VERSION 5.8 ;
BUSBITCHARS "[]" ;
DIVIDERCHAR "/" ;
UNITS
    DATABASE MICRONS 1000 ;
END UNITS

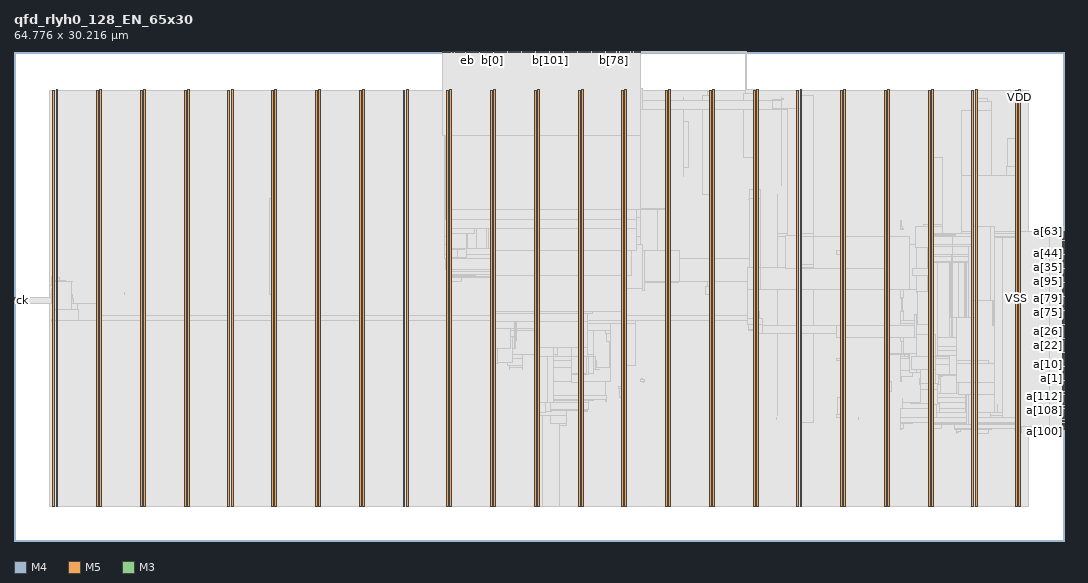
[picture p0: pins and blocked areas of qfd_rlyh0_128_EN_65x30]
MACRO qfd_rlyh0_128_EN_65x30
  FOREIGN qfd_rlyh0_128_EN_65x30 0 0 ;
  CLASS BLOCK ;
  SIZE 64.776 BY 30.216 ;
  PIN a[0]
    DIRECTION INPUT ;
    USE SIGNAL ;
    PORT
      LAYER M4 ;
        RECT  64.692 9.936 64.776 9.96 ;
    END
  END a[0]
  PIN a[100]
    DIRECTION INPUT ;
    USE SIGNAL ;
    PORT
      LAYER M4 ;
        RECT  64.692 7.248 64.776 7.272 ;
    END
  END a[100]
  PIN a[101]
    DIRECTION INPUT ;
    USE SIGNAL ;
    PORT
      LAYER M4 ;
        RECT  64.692 7.344 64.776 7.368 ;
    END
  END a[101]
  PIN a[102]
    DIRECTION INPUT ;
    USE SIGNAL ;
    PORT
      LAYER M4 ;
        RECT  64.692 7.44 64.776 7.464 ;
    END
  END a[102]
  PIN a[103]
    DIRECTION INPUT ;
    USE SIGNAL ;
    PORT
      LAYER M4 ;
        RECT  64.692 7.536 64.776 7.56 ;
    END
  END a[103]
  PIN a[104]
    DIRECTION INPUT ;
    USE SIGNAL ;
    PORT
      LAYER M4 ;
        RECT  64.692 7.632 64.776 7.656 ;
    END
  END a[104]
  PIN a[105]
    DIRECTION INPUT ;
    USE SIGNAL ;
    PORT
      LAYER M4 ;
        RECT  64.692 7.728 64.776 7.752 ;
    END
  END a[105]
  PIN a[106]
    DIRECTION INPUT ;
    USE SIGNAL ;
    PORT
      LAYER M4 ;
        RECT  64.692 7.824 64.776 7.848 ;
    END
  END a[106]
  PIN a[107]
    DIRECTION INPUT ;
    USE SIGNAL ;
    PORT
      LAYER M4 ;
        RECT  64.692 7.92 64.776 7.944 ;
    END
  END a[107]
  PIN a[108]
    DIRECTION INPUT ;
    USE SIGNAL ;
    PORT
      LAYER M4 ;
        RECT  64.692 8.016 64.776 8.04 ;
    END
  END a[108]
  PIN a[109]
    DIRECTION INPUT ;
    USE SIGNAL ;
    PORT
      LAYER M4 ;
        RECT  64.692 8.112 64.776 8.136 ;
    END
  END a[109]
  PIN a[10]
    DIRECTION INPUT ;
    USE SIGNAL ;
    PORT
      LAYER M4 ;
        RECT  64.692 10.896 64.776 10.92 ;
    END
  END a[10]
  PIN a[110]
    DIRECTION INPUT ;
    USE SIGNAL ;
    PORT
      LAYER M4 ;
        RECT  64.692 8.208 64.776 8.232 ;
    END
  END a[110]
  PIN a[111]
    DIRECTION INPUT ;
    USE SIGNAL ;
    PORT
      LAYER M4 ;
        RECT  64.692 8.304 64.776 8.328 ;
    END
  END a[111]
  PIN a[112]
    DIRECTION INPUT ;
    USE SIGNAL ;
    PORT
      LAYER M4 ;
        RECT  64.692 8.4 64.776 8.424 ;
    END
  END a[112]
  PIN a[113]
    DIRECTION INPUT ;
    USE SIGNAL ;
    PORT
      LAYER M4 ;
        RECT  64.692 8.496 64.776 8.52 ;
    END
  END a[113]
  PIN a[114]
    DIRECTION INPUT ;
    USE SIGNAL ;
    PORT
      LAYER M4 ;
        RECT  64.692 8.592 64.776 8.616 ;
    END
  END a[114]
  PIN a[115]
    DIRECTION INPUT ;
    USE SIGNAL ;
    PORT
      LAYER M4 ;
        RECT  64.692 8.688 64.776 8.712 ;
    END
  END a[115]
  PIN a[116]
    DIRECTION INPUT ;
    USE SIGNAL ;
    PORT
      LAYER M4 ;
        RECT  64.692 8.784 64.776 8.808 ;
    END
  END a[116]
  PIN a[117]
    DIRECTION INPUT ;
    USE SIGNAL ;
    PORT
      LAYER M4 ;
        RECT  64.692 8.88 64.776 8.904 ;
    END
  END a[117]
  PIN a[118]
    DIRECTION INPUT ;
    USE SIGNAL ;
    PORT
      LAYER M4 ;
        RECT  64.692 8.976 64.776 9 ;
    END
  END a[118]
  PIN a[119]
    DIRECTION INPUT ;
    USE SIGNAL ;
    PORT
      LAYER M4 ;
        RECT  64.692 9.072 64.776 9.096 ;
    END
  END a[119]
  PIN a[11]
    DIRECTION INPUT ;
    USE SIGNAL ;
    PORT
      LAYER M4 ;
        RECT  64.692 10.992 64.776 11.016 ;
    END
  END a[11]
  PIN a[120]
    DIRECTION INPUT ;
    USE SIGNAL ;
    PORT
      LAYER M4 ;
        RECT  64.692 9.168 64.776 9.192 ;
    END
  END a[120]
  PIN a[121]
    DIRECTION INPUT ;
    USE SIGNAL ;
    PORT
      LAYER M4 ;
        RECT  64.692 9.264 64.776 9.288 ;
    END
  END a[121]
  PIN a[122]
    DIRECTION INPUT ;
    USE SIGNAL ;
    PORT
      LAYER M4 ;
        RECT  64.692 9.36 64.776 9.384 ;
    END
  END a[122]
  PIN a[123]
    DIRECTION INPUT ;
    USE SIGNAL ;
    PORT
      LAYER M4 ;
        RECT  64.692 9.456 64.776 9.48 ;
    END
  END a[123]
  PIN a[124]
    DIRECTION INPUT ;
    USE SIGNAL ;
    PORT
      LAYER M4 ;
        RECT  64.692 9.552 64.776 9.576 ;
    END
  END a[124]
  PIN a[125]
    DIRECTION INPUT ;
    USE SIGNAL ;
    PORT
      LAYER M4 ;
        RECT  64.692 9.648 64.776 9.672 ;
    END
  END a[125]
  PIN a[126]
    DIRECTION INPUT ;
    USE SIGNAL ;
    PORT
      LAYER M4 ;
        RECT  64.692 9.744 64.776 9.768 ;
    END
  END a[126]
  PIN a[127]
    DIRECTION INPUT ;
    USE SIGNAL ;
    PORT
      LAYER M4 ;
        RECT  64.692 9.84 64.776 9.864 ;
    END
  END a[127]
  PIN a[12]
    DIRECTION INPUT ;
    USE SIGNAL ;
    PORT
      LAYER M4 ;
        RECT  64.692 11.088 64.776 11.112 ;
    END
  END a[12]
  PIN a[13]
    DIRECTION INPUT ;
    USE SIGNAL ;
    PORT
      LAYER M4 ;
        RECT  64.692 11.184 64.776 11.208 ;
    END
  END a[13]
  PIN a[14]
    DIRECTION INPUT ;
    USE SIGNAL ;
    PORT
      LAYER M4 ;
        RECT  64.692 11.28 64.776 11.304 ;
    END
  END a[14]
  PIN a[15]
    DIRECTION INPUT ;
    USE SIGNAL ;
    PORT
      LAYER M4 ;
        RECT  64.692 11.376 64.776 11.4 ;
    END
  END a[15]
  PIN a[16]
    DIRECTION INPUT ;
    USE SIGNAL ;
    PORT
      LAYER M4 ;
        RECT  64.692 11.472 64.776 11.496 ;
    END
  END a[16]
  PIN a[17]
    DIRECTION INPUT ;
    USE SIGNAL ;
    PORT
      LAYER M4 ;
        RECT  64.692 11.568 64.776 11.592 ;
    END
  END a[17]
  PIN a[18]
    DIRECTION INPUT ;
    USE SIGNAL ;
    PORT
      LAYER M4 ;
        RECT  64.692 11.664 64.776 11.688 ;
    END
  END a[18]
  PIN a[19]
    DIRECTION INPUT ;
    USE SIGNAL ;
    PORT
      LAYER M4 ;
        RECT  64.692 11.76 64.776 11.784 ;
    END
  END a[19]
  PIN a[1]
    DIRECTION INPUT ;
    USE SIGNAL ;
    PORT
      LAYER M4 ;
        RECT  64.692 10.032 64.776 10.056 ;
    END
  END a[1]
  PIN a[20]
    DIRECTION INPUT ;
    USE SIGNAL ;
    PORT
      LAYER M4 ;
        RECT  64.692 11.856 64.776 11.88 ;
    END
  END a[20]
  PIN a[21]
    DIRECTION INPUT ;
    USE SIGNAL ;
    PORT
      LAYER M4 ;
        RECT  64.692 11.952 64.776 11.976 ;
    END
  END a[21]
  PIN a[22]
    DIRECTION INPUT ;
    USE SIGNAL ;
    PORT
      LAYER M4 ;
        RECT  64.692 12.048 64.776 12.072 ;
    END
  END a[22]
  PIN a[23]
    DIRECTION INPUT ;
    USE SIGNAL ;
    PORT
      LAYER M4 ;
        RECT  64.692 12.144 64.776 12.168 ;
    END
  END a[23]
  PIN a[24]
    DIRECTION INPUT ;
    USE SIGNAL ;
    PORT
      LAYER M4 ;
        RECT  64.692 12.24 64.776 12.264 ;
    END
  END a[24]
  PIN a[25]
    DIRECTION INPUT ;
    USE SIGNAL ;
    PORT
      LAYER M4 ;
        RECT  64.692 12.336 64.776 12.36 ;
    END
  END a[25]
  PIN a[26]
    DIRECTION INPUT ;
    USE SIGNAL ;
    PORT
      LAYER M4 ;
        RECT  64.692 12.432 64.776 12.456 ;
    END
  END a[26]
  PIN a[27]
    DIRECTION INPUT ;
    USE SIGNAL ;
    PORT
      LAYER M4 ;
        RECT  64.692 12.528 64.776 12.552 ;
    END
  END a[27]
  PIN a[28]
    DIRECTION INPUT ;
    USE SIGNAL ;
    PORT
      LAYER M4 ;
        RECT  64.692 12.624 64.776 12.648 ;
    END
  END a[28]
  PIN a[29]
    DIRECTION INPUT ;
    USE SIGNAL ;
    PORT
      LAYER M4 ;
        RECT  64.692 12.72 64.776 12.744 ;
    END
  END a[29]
  PIN a[2]
    DIRECTION INPUT ;
    USE SIGNAL ;
    PORT
      LAYER M4 ;
        RECT  64.692 10.128 64.776 10.152 ;
    END
  END a[2]
  PIN a[30]
    DIRECTION INPUT ;
    USE SIGNAL ;
    PORT
      LAYER M4 ;
        RECT  64.692 12.816 64.776 12.84 ;
    END
  END a[30]
  PIN a[31]
    DIRECTION INPUT ;
    USE SIGNAL ;
    PORT
      LAYER M4 ;
        RECT  64.692 12.912 64.776 12.936 ;
    END
  END a[31]
  PIN a[32]
    DIRECTION INPUT ;
    USE SIGNAL ;
    PORT
      LAYER M4 ;
        RECT  64.692 16.08 64.776 16.104 ;
    END
  END a[32]
  PIN a[33]
    DIRECTION INPUT ;
    USE SIGNAL ;
    PORT
      LAYER M4 ;
        RECT  64.692 16.176 64.776 16.2 ;
    END
  END a[33]
  PIN a[34]
    DIRECTION INPUT ;
    USE SIGNAL ;
    PORT
      LAYER M4 ;
        RECT  64.692 16.272 64.776 16.296 ;
    END
  END a[34]
  PIN a[35]
    DIRECTION INPUT ;
    USE SIGNAL ;
    PORT
      LAYER M4 ;
        RECT  64.692 16.368 64.776 16.392 ;
    END
  END a[35]
  PIN a[36]
    DIRECTION INPUT ;
    USE SIGNAL ;
    PORT
      LAYER M4 ;
        RECT  64.692 16.464 64.776 16.488 ;
    END
  END a[36]
  PIN a[37]
    DIRECTION INPUT ;
    USE SIGNAL ;
    PORT
      LAYER M4 ;
        RECT  64.692 16.56 64.776 16.584 ;
    END
  END a[37]
  PIN a[38]
    DIRECTION INPUT ;
    USE SIGNAL ;
    PORT
      LAYER M4 ;
        RECT  64.692 16.656 64.776 16.68 ;
    END
  END a[38]
  PIN a[39]
    DIRECTION INPUT ;
    USE SIGNAL ;
    PORT
      LAYER M4 ;
        RECT  64.692 16.752 64.776 16.776 ;
    END
  END a[39]
  PIN a[3]
    DIRECTION INPUT ;
    USE SIGNAL ;
    PORT
      LAYER M4 ;
        RECT  64.692 10.224 64.776 10.248 ;
    END
  END a[3]
  PIN a[40]
    DIRECTION INPUT ;
    USE SIGNAL ;
    PORT
      LAYER M4 ;
        RECT  64.692 16.848 64.776 16.872 ;
    END
  END a[40]
  PIN a[41]
    DIRECTION INPUT ;
    USE SIGNAL ;
    PORT
      LAYER M4 ;
        RECT  64.692 16.944 64.776 16.968 ;
    END
  END a[41]
  PIN a[42]
    DIRECTION INPUT ;
    USE SIGNAL ;
    PORT
      LAYER M4 ;
        RECT  64.692 17.04 64.776 17.064 ;
    END
  END a[42]
  PIN a[43]
    DIRECTION INPUT ;
    USE SIGNAL ;
    PORT
      LAYER M4 ;
        RECT  64.692 17.136 64.776 17.16 ;
    END
  END a[43]
  PIN a[44]
    DIRECTION INPUT ;
    USE SIGNAL ;
    PORT
      LAYER M4 ;
        RECT  64.692 17.232 64.776 17.256 ;
    END
  END a[44]
  PIN a[45]
    DIRECTION INPUT ;
    USE SIGNAL ;
    PORT
      LAYER M4 ;
        RECT  64.692 17.328 64.776 17.352 ;
    END
  END a[45]
  PIN a[46]
    DIRECTION INPUT ;
    USE SIGNAL ;
    PORT
      LAYER M4 ;
        RECT  64.692 17.424 64.776 17.448 ;
    END
  END a[46]
  PIN a[47]
    DIRECTION INPUT ;
    USE SIGNAL ;
    PORT
      LAYER M4 ;
        RECT  64.692 17.52 64.776 17.544 ;
    END
  END a[47]
  PIN a[48]
    DIRECTION INPUT ;
    USE SIGNAL ;
    PORT
      LAYER M4 ;
        RECT  64.692 17.616 64.776 17.64 ;
    END
  END a[48]
  PIN a[49]
    DIRECTION INPUT ;
    USE SIGNAL ;
    PORT
      LAYER M4 ;
        RECT  64.692 17.712 64.776 17.736 ;
    END
  END a[49]
  PIN a[4]
    DIRECTION INPUT ;
    USE SIGNAL ;
    PORT
      LAYER M4 ;
        RECT  64.692 10.32 64.776 10.344 ;
    END
  END a[4]
  PIN a[50]
    DIRECTION INPUT ;
    USE SIGNAL ;
    PORT
      LAYER M4 ;
        RECT  64.692 17.808 64.776 17.832 ;
    END
  END a[50]
  PIN a[51]
    DIRECTION INPUT ;
    USE SIGNAL ;
    PORT
      LAYER M4 ;
        RECT  64.692 17.904 64.776 17.928 ;
    END
  END a[51]
  PIN a[52]
    DIRECTION INPUT ;
    USE SIGNAL ;
    PORT
      LAYER M4 ;
        RECT  64.692 18 64.776 18.024 ;
    END
  END a[52]
  PIN a[53]
    DIRECTION INPUT ;
    USE SIGNAL ;
    PORT
      LAYER M4 ;
        RECT  64.692 18.096 64.776 18.12 ;
    END
  END a[53]
  PIN a[54]
    DIRECTION INPUT ;
    USE SIGNAL ;
    PORT
      LAYER M4 ;
        RECT  64.692 18.192 64.776 18.216 ;
    END
  END a[54]
  PIN a[55]
    DIRECTION INPUT ;
    USE SIGNAL ;
    PORT
      LAYER M4 ;
        RECT  64.692 18.288 64.776 18.312 ;
    END
  END a[55]
  PIN a[56]
    DIRECTION INPUT ;
    USE SIGNAL ;
    PORT
      LAYER M4 ;
        RECT  64.692 18.384 64.776 18.408 ;
    END
  END a[56]
  PIN a[57]
    DIRECTION INPUT ;
    USE SIGNAL ;
    PORT
      LAYER M4 ;
        RECT  64.692 18.48 64.776 18.504 ;
    END
  END a[57]
  PIN a[58]
    DIRECTION INPUT ;
    USE SIGNAL ;
    PORT
      LAYER M4 ;
        RECT  64.692 18.576 64.776 18.6 ;
    END
  END a[58]
  PIN a[59]
    DIRECTION INPUT ;
    USE SIGNAL ;
    PORT
      LAYER M4 ;
        RECT  64.692 18.672 64.776 18.696 ;
    END
  END a[59]
  PIN a[5]
    DIRECTION INPUT ;
    USE SIGNAL ;
    PORT
      LAYER M4 ;
        RECT  64.692 10.416 64.776 10.44 ;
    END
  END a[5]
  PIN a[60]
    DIRECTION INPUT ;
    USE SIGNAL ;
    PORT
      LAYER M4 ;
        RECT  64.692 18.768 64.776 18.792 ;
    END
  END a[60]
  PIN a[61]
    DIRECTION INPUT ;
    USE SIGNAL ;
    PORT
      LAYER M4 ;
        RECT  64.692 18.864 64.776 18.888 ;
    END
  END a[61]
  PIN a[62]
    DIRECTION INPUT ;
    USE SIGNAL ;
    PORT
      LAYER M4 ;
        RECT  64.692 18.96 64.776 18.984 ;
    END
  END a[62]
  PIN a[63]
    DIRECTION INPUT ;
    USE SIGNAL ;
    PORT
      LAYER M4 ;
        RECT  64.692 19.056 64.776 19.08 ;
    END
  END a[63]
  PIN a[64]
    DIRECTION INPUT ;
    USE SIGNAL ;
    PORT
      LAYER M4 ;
        RECT  64.692 13.008 64.776 13.032 ;
    END
  END a[64]
  PIN a[65]
    DIRECTION INPUT ;
    USE SIGNAL ;
    PORT
      LAYER M4 ;
        RECT  64.692 13.104 64.776 13.128 ;
    END
  END a[65]
  PIN a[66]
    DIRECTION INPUT ;
    USE SIGNAL ;
    PORT
      LAYER M4 ;
        RECT  64.692 13.2 64.776 13.224 ;
    END
  END a[66]
  PIN a[67]
    DIRECTION INPUT ;
    USE SIGNAL ;
    PORT
      LAYER M4 ;
        RECT  64.692 13.296 64.776 13.32 ;
    END
  END a[67]
  PIN a[68]
    DIRECTION INPUT ;
    USE SIGNAL ;
    PORT
      LAYER M4 ;
        RECT  64.692 13.392 64.776 13.416 ;
    END
  END a[68]
  PIN a[69]
    DIRECTION INPUT ;
    USE SIGNAL ;
    PORT
      LAYER M4 ;
        RECT  64.692 13.488 64.776 13.512 ;
    END
  END a[69]
  PIN a[6]
    DIRECTION INPUT ;
    USE SIGNAL ;
    PORT
      LAYER M4 ;
        RECT  64.692 10.512 64.776 10.536 ;
    END
  END a[6]
  PIN a[70]
    DIRECTION INPUT ;
    USE SIGNAL ;
    PORT
      LAYER M4 ;
        RECT  64.692 13.584 64.776 13.608 ;
    END
  END a[70]
  PIN a[71]
    DIRECTION INPUT ;
    USE SIGNAL ;
    PORT
      LAYER M4 ;
        RECT  64.692 13.68 64.776 13.704 ;
    END
  END a[71]
  PIN a[72]
    DIRECTION INPUT ;
    USE SIGNAL ;
    PORT
      LAYER M4 ;
        RECT  64.692 13.776 64.776 13.8 ;
    END
  END a[72]
  PIN a[73]
    DIRECTION INPUT ;
    USE SIGNAL ;
    PORT
      LAYER M4 ;
        RECT  64.692 13.872 64.776 13.896 ;
    END
  END a[73]
  PIN a[74]
    DIRECTION INPUT ;
    USE SIGNAL ;
    PORT
      LAYER M4 ;
        RECT  64.692 13.968 64.776 13.992 ;
    END
  END a[74]
  PIN a[75]
    DIRECTION INPUT ;
    USE SIGNAL ;
    PORT
      LAYER M4 ;
        RECT  64.692 14.064 64.776 14.088 ;
    END
  END a[75]
  PIN a[76]
    DIRECTION INPUT ;
    USE SIGNAL ;
    PORT
      LAYER M4 ;
        RECT  64.692 14.16 64.776 14.184 ;
    END
  END a[76]
  PIN a[77]
    DIRECTION INPUT ;
    USE SIGNAL ;
    PORT
      LAYER M4 ;
        RECT  64.692 14.256 64.776 14.28 ;
    END
  END a[77]
  PIN a[78]
    DIRECTION INPUT ;
    USE SIGNAL ;
    PORT
      LAYER M4 ;
        RECT  64.692 14.352 64.776 14.376 ;
    END
  END a[78]
  PIN a[79]
    DIRECTION INPUT ;
    USE SIGNAL ;
    PORT
      LAYER M4 ;
        RECT  64.692 14.448 64.776 14.472 ;
    END
  END a[79]
  PIN a[7]
    DIRECTION INPUT ;
    USE SIGNAL ;
    PORT
      LAYER M4 ;
        RECT  64.692 10.608 64.776 10.632 ;
    END
  END a[7]
  PIN a[80]
    DIRECTION INPUT ;
    USE SIGNAL ;
    PORT
      LAYER M4 ;
        RECT  64.692 14.544 64.776 14.568 ;
    END
  END a[80]
  PIN a[81]
    DIRECTION INPUT ;
    USE SIGNAL ;
    PORT
      LAYER M4 ;
        RECT  64.692 14.64 64.776 14.664 ;
    END
  END a[81]
  PIN a[82]
    DIRECTION INPUT ;
    USE SIGNAL ;
    PORT
      LAYER M4 ;
        RECT  64.692 14.736 64.776 14.76 ;
    END
  END a[82]
  PIN a[83]
    DIRECTION INPUT ;
    USE SIGNAL ;
    PORT
      LAYER M4 ;
        RECT  64.692 14.832 64.776 14.856 ;
    END
  END a[83]
  PIN a[84]
    DIRECTION INPUT ;
    USE SIGNAL ;
    PORT
      LAYER M4 ;
        RECT  64.692 14.928 64.776 14.952 ;
    END
  END a[84]
  PIN a[85]
    DIRECTION INPUT ;
    USE SIGNAL ;
    PORT
      LAYER M4 ;
        RECT  64.692 15.024 64.776 15.048 ;
    END
  END a[85]
  PIN a[86]
    DIRECTION INPUT ;
    USE SIGNAL ;
    PORT
      LAYER M4 ;
        RECT  64.692 15.12 64.776 15.144 ;
    END
  END a[86]
  PIN a[87]
    DIRECTION INPUT ;
    USE SIGNAL ;
    PORT
      LAYER M4 ;
        RECT  64.692 15.216 64.776 15.24 ;
    END
  END a[87]
  PIN a[88]
    DIRECTION INPUT ;
    USE SIGNAL ;
    PORT
      LAYER M4 ;
        RECT  64.692 15.312 64.776 15.336 ;
    END
  END a[88]
  PIN a[89]
    DIRECTION INPUT ;
    USE SIGNAL ;
    PORT
      LAYER M4 ;
        RECT  64.692 15.408 64.776 15.432 ;
    END
  END a[89]
  PIN a[8]
    DIRECTION INPUT ;
    USE SIGNAL ;
    PORT
      LAYER M4 ;
        RECT  64.692 10.704 64.776 10.728 ;
    END
  END a[8]
  PIN a[90]
    DIRECTION INPUT ;
    USE SIGNAL ;
    PORT
      LAYER M4 ;
        RECT  64.692 15.504 64.776 15.528 ;
    END
  END a[90]
  PIN a[91]
    DIRECTION INPUT ;
    USE SIGNAL ;
    PORT
      LAYER M4 ;
        RECT  64.692 15.6 64.776 15.624 ;
    END
  END a[91]
  PIN a[92]
    DIRECTION INPUT ;
    USE SIGNAL ;
    PORT
      LAYER M4 ;
        RECT  64.692 15.696 64.776 15.72 ;
    END
  END a[92]
  PIN a[93]
    DIRECTION INPUT ;
    USE SIGNAL ;
    PORT
      LAYER M4 ;
        RECT  64.692 15.792 64.776 15.816 ;
    END
  END a[93]
  PIN a[94]
    DIRECTION INPUT ;
    USE SIGNAL ;
    PORT
      LAYER M4 ;
        RECT  64.692 15.888 64.776 15.912 ;
    END
  END a[94]
  PIN a[95]
    DIRECTION INPUT ;
    USE SIGNAL ;
    PORT
      LAYER M4 ;
        RECT  64.692 15.984 64.776 16.008 ;
    END
  END a[95]
  PIN a[96]
    DIRECTION INPUT ;
    USE SIGNAL ;
    PORT
      LAYER M4 ;
        RECT  64.692 6.864 64.776 6.888 ;
    END
  END a[96]
  PIN a[97]
    DIRECTION INPUT ;
    USE SIGNAL ;
    PORT
      LAYER M4 ;
        RECT  64.692 6.96 64.776 6.984 ;
    END
  END a[97]
  PIN a[98]
    DIRECTION INPUT ;
    USE SIGNAL ;
    PORT
      LAYER M4 ;
        RECT  64.692 7.056 64.776 7.08 ;
    END
  END a[98]
  PIN a[99]
    DIRECTION INPUT ;
    USE SIGNAL ;
    PORT
      LAYER M4 ;
        RECT  64.692 7.152 64.776 7.176 ;
    END
  END a[99]
  PIN a[9]
    DIRECTION INPUT ;
    USE SIGNAL ;
    PORT
      LAYER M4 ;
        RECT  64.692 10.8 64.776 10.824 ;
    END
  END a[9]
  PIN b[0]
    DIRECTION OUTPUT ;
    USE SIGNAL ;
    PORT
      LAYER M5 ;
        RECT  29.52 30.132 29.544 30.216 ;
    END
  END b[0]
  PIN b[100]
    DIRECTION OUTPUT ;
    USE SIGNAL ;
    PORT
      LAYER M5 ;
        RECT  32.976 30.132 33 30.216 ;
    END
  END b[100]
  PIN b[101]
    DIRECTION OUTPUT ;
    USE SIGNAL ;
    PORT
      LAYER M5 ;
        RECT  33.072 30.132 33.096 30.216 ;
    END
  END b[101]
  PIN b[102]
    DIRECTION OUTPUT ;
    USE SIGNAL ;
    PORT
      LAYER M5 ;
        RECT  33.168 30.132 33.192 30.216 ;
    END
  END b[102]
  PIN b[103]
    DIRECTION OUTPUT ;
    USE SIGNAL ;
    PORT
      LAYER M5 ;
        RECT  33.264 30.132 33.288 30.216 ;
    END
  END b[103]
  PIN b[104]
    DIRECTION OUTPUT ;
    USE SIGNAL ;
    PORT
      LAYER M5 ;
        RECT  33.36 30.132 33.384 30.216 ;
    END
  END b[104]
  PIN b[105]
    DIRECTION OUTPUT ;
    USE SIGNAL ;
    PORT
      LAYER M5 ;
        RECT  33.456 30.132 33.48 30.216 ;
    END
  END b[105]
  PIN b[106]
    DIRECTION OUTPUT ;
    USE SIGNAL ;
    PORT
      LAYER M5 ;
        RECT  33.552 30.132 33.576 30.216 ;
    END
  END b[106]
  PIN b[107]
    DIRECTION OUTPUT ;
    USE SIGNAL ;
    PORT
      LAYER M5 ;
        RECT  33.648 30.132 33.672 30.216 ;
    END
  END b[107]
  PIN b[108]
    DIRECTION OUTPUT ;
    USE SIGNAL ;
    PORT
      LAYER M5 ;
        RECT  33.744 30.132 33.768 30.216 ;
    END
  END b[108]
  PIN b[109]
    DIRECTION OUTPUT ;
    USE SIGNAL ;
    PORT
      LAYER M5 ;
        RECT  33.84 30.132 33.864 30.216 ;
    END
  END b[109]
  PIN b[10]
    DIRECTION OUTPUT ;
    USE SIGNAL ;
    PORT
      LAYER M5 ;
        RECT  30.48 30.132 30.504 30.216 ;
    END
  END b[10]
  PIN b[110]
    DIRECTION OUTPUT ;
    USE SIGNAL ;
    PORT
      LAYER M5 ;
        RECT  33.936 30.132 33.96 30.216 ;
    END
  END b[110]
  PIN b[111]
    DIRECTION OUTPUT ;
    USE SIGNAL ;
    PORT
      LAYER M5 ;
        RECT  34.032 30.132 34.056 30.216 ;
    END
  END b[111]
  PIN b[112]
    DIRECTION OUTPUT ;
    USE SIGNAL ;
    PORT
      LAYER M5 ;
        RECT  34.128 30.132 34.152 30.216 ;
    END
  END b[112]
  PIN b[113]
    DIRECTION OUTPUT ;
    USE SIGNAL ;
    PORT
      LAYER M5 ;
        RECT  34.224 30.132 34.248 30.216 ;
    END
  END b[113]
  PIN b[114]
    DIRECTION OUTPUT ;
    USE SIGNAL ;
    PORT
      LAYER M5 ;
        RECT  34.32 30.132 34.344 30.216 ;
    END
  END b[114]
  PIN b[115]
    DIRECTION OUTPUT ;
    USE SIGNAL ;
    PORT
      LAYER M5 ;
        RECT  34.416 30.132 34.44 30.216 ;
    END
  END b[115]
  PIN b[116]
    DIRECTION OUTPUT ;
    USE SIGNAL ;
    PORT
      LAYER M5 ;
        RECT  34.512 30.132 34.536 30.216 ;
    END
  END b[116]
  PIN b[117]
    DIRECTION OUTPUT ;
    USE SIGNAL ;
    PORT
      LAYER M5 ;
        RECT  34.608 30.132 34.632 30.216 ;
    END
  END b[117]
  PIN b[118]
    DIRECTION OUTPUT ;
    USE SIGNAL ;
    PORT
      LAYER M5 ;
        RECT  34.704 30.132 34.728 30.216 ;
    END
  END b[118]
  PIN b[119]
    DIRECTION OUTPUT ;
    USE SIGNAL ;
    PORT
      LAYER M5 ;
        RECT  34.8 30.132 34.824 30.216 ;
    END
  END b[119]
  PIN b[11]
    DIRECTION OUTPUT ;
    USE SIGNAL ;
    PORT
      LAYER M5 ;
        RECT  30.576 30.132 30.6 30.216 ;
    END
  END b[11]
  PIN b[120]
    DIRECTION OUTPUT ;
    USE SIGNAL ;
    PORT
      LAYER M5 ;
        RECT  34.896 30.132 34.92 30.216 ;
    END
  END b[120]
  PIN b[121]
    DIRECTION OUTPUT ;
    USE SIGNAL ;
    PORT
      LAYER M5 ;
        RECT  34.992 30.132 35.016 30.216 ;
    END
  END b[121]
  PIN b[122]
    DIRECTION OUTPUT ;
    USE SIGNAL ;
    PORT
      LAYER M5 ;
        RECT  35.088 30.132 35.112 30.216 ;
    END
  END b[122]
  PIN b[123]
    DIRECTION OUTPUT ;
    USE SIGNAL ;
    PORT
      LAYER M5 ;
        RECT  35.184 30.132 35.208 30.216 ;
    END
  END b[123]
  PIN b[124]
    DIRECTION OUTPUT ;
    USE SIGNAL ;
    PORT
      LAYER M5 ;
        RECT  35.28 30.132 35.304 30.216 ;
    END
  END b[124]
  PIN b[125]
    DIRECTION OUTPUT ;
    USE SIGNAL ;
    PORT
      LAYER M5 ;
        RECT  35.376 30.132 35.4 30.216 ;
    END
  END b[125]
  PIN b[126]
    DIRECTION OUTPUT ;
    USE SIGNAL ;
    PORT
      LAYER M5 ;
        RECT  35.472 30.132 35.496 30.216 ;
    END
  END b[126]
  PIN b[127]
    DIRECTION OUTPUT ;
    USE SIGNAL ;
    PORT
      LAYER M5 ;
        RECT  35.568 30.132 35.592 30.216 ;
    END
  END b[127]
  PIN b[12]
    DIRECTION OUTPUT ;
    USE SIGNAL ;
    PORT
      LAYER M5 ;
        RECT  30.672 30.132 30.696 30.216 ;
    END
  END b[12]
  PIN b[13]
    DIRECTION OUTPUT ;
    USE SIGNAL ;
    PORT
      LAYER M5 ;
        RECT  30.768 30.132 30.792 30.216 ;
    END
  END b[13]
  PIN b[14]
    DIRECTION OUTPUT ;
    USE SIGNAL ;
    PORT
      LAYER M5 ;
        RECT  30.864 30.132 30.888 30.216 ;
    END
  END b[14]
  PIN b[15]
    DIRECTION OUTPUT ;
    USE SIGNAL ;
    PORT
      LAYER M5 ;
        RECT  30.96 30.132 30.984 30.216 ;
    END
  END b[15]
  PIN b[16]
    DIRECTION OUTPUT ;
    USE SIGNAL ;
    PORT
      LAYER M5 ;
        RECT  31.056 30.132 31.08 30.216 ;
    END
  END b[16]
  PIN b[17]
    DIRECTION OUTPUT ;
    USE SIGNAL ;
    PORT
      LAYER M5 ;
        RECT  31.152 30.132 31.176 30.216 ;
    END
  END b[17]
  PIN b[18]
    DIRECTION OUTPUT ;
    USE SIGNAL ;
    PORT
      LAYER M5 ;
        RECT  31.248 30.132 31.272 30.216 ;
    END
  END b[18]
  PIN b[19]
    DIRECTION OUTPUT ;
    USE SIGNAL ;
    PORT
      LAYER M5 ;
        RECT  31.344 30.132 31.368 30.216 ;
    END
  END b[19]
  PIN b[1]
    DIRECTION OUTPUT ;
    USE SIGNAL ;
    PORT
      LAYER M5 ;
        RECT  29.616 30.132 29.64 30.216 ;
    END
  END b[1]
  PIN b[20]
    DIRECTION OUTPUT ;
    USE SIGNAL ;
    PORT
      LAYER M5 ;
        RECT  31.44 30.132 31.464 30.216 ;
    END
  END b[20]
  PIN b[21]
    DIRECTION OUTPUT ;
    USE SIGNAL ;
    PORT
      LAYER M5 ;
        RECT  31.536 30.132 31.56 30.216 ;
    END
  END b[21]
  PIN b[22]
    DIRECTION OUTPUT ;
    USE SIGNAL ;
    PORT
      LAYER M5 ;
        RECT  31.632 30.132 31.656 30.216 ;
    END
  END b[22]
  PIN b[23]
    DIRECTION OUTPUT ;
    USE SIGNAL ;
    PORT
      LAYER M5 ;
        RECT  31.728 30.132 31.752 30.216 ;
    END
  END b[23]
  PIN b[24]
    DIRECTION OUTPUT ;
    USE SIGNAL ;
    PORT
      LAYER M5 ;
        RECT  31.824 30.132 31.848 30.216 ;
    END
  END b[24]
  PIN b[25]
    DIRECTION OUTPUT ;
    USE SIGNAL ;
    PORT
      LAYER M5 ;
        RECT  31.92 30.132 31.944 30.216 ;
    END
  END b[25]
  PIN b[26]
    DIRECTION OUTPUT ;
    USE SIGNAL ;
    PORT
      LAYER M5 ;
        RECT  32.016 30.132 32.04 30.216 ;
    END
  END b[26]
  PIN b[27]
    DIRECTION OUTPUT ;
    USE SIGNAL ;
    PORT
      LAYER M5 ;
        RECT  32.112 30.132 32.136 30.216 ;
    END
  END b[27]
  PIN b[28]
    DIRECTION OUTPUT ;
    USE SIGNAL ;
    PORT
      LAYER M5 ;
        RECT  32.208 30.132 32.232 30.216 ;
    END
  END b[28]
  PIN b[29]
    DIRECTION OUTPUT ;
    USE SIGNAL ;
    PORT
      LAYER M5 ;
        RECT  32.304 30.132 32.328 30.216 ;
    END
  END b[29]
  PIN b[2]
    DIRECTION OUTPUT ;
    USE SIGNAL ;
    PORT
      LAYER M5 ;
        RECT  29.712 30.132 29.736 30.216 ;
    END
  END b[2]
  PIN b[30]
    DIRECTION OUTPUT ;
    USE SIGNAL ;
    PORT
      LAYER M5 ;
        RECT  32.4 30.132 32.424 30.216 ;
    END
  END b[30]
  PIN b[31]
    DIRECTION OUTPUT ;
    USE SIGNAL ;
    PORT
      LAYER M5 ;
        RECT  32.496 30.132 32.52 30.216 ;
    END
  END b[31]
  PIN b[32]
    DIRECTION OUTPUT ;
    USE SIGNAL ;
    PORT
      LAYER M5 ;
        RECT  26.448 30.132 26.472 30.216 ;
    END
  END b[32]
  PIN b[33]
    DIRECTION OUTPUT ;
    USE SIGNAL ;
    PORT
      LAYER M5 ;
        RECT  26.544 30.132 26.568 30.216 ;
    END
  END b[33]
  PIN b[34]
    DIRECTION OUTPUT ;
    USE SIGNAL ;
    PORT
      LAYER M5 ;
        RECT  26.64 30.132 26.664 30.216 ;
    END
  END b[34]
  PIN b[35]
    DIRECTION OUTPUT ;
    USE SIGNAL ;
    PORT
      LAYER M5 ;
        RECT  26.736 30.132 26.76 30.216 ;
    END
  END b[35]
  PIN b[36]
    DIRECTION OUTPUT ;
    USE SIGNAL ;
    PORT
      LAYER M5 ;
        RECT  26.832 30.132 26.856 30.216 ;
    END
  END b[36]
  PIN b[37]
    DIRECTION OUTPUT ;
    USE SIGNAL ;
    PORT
      LAYER M5 ;
        RECT  26.928 30.132 26.952 30.216 ;
    END
  END b[37]
  PIN b[38]
    DIRECTION OUTPUT ;
    USE SIGNAL ;
    PORT
      LAYER M5 ;
        RECT  27.024 30.132 27.048 30.216 ;
    END
  END b[38]
  PIN b[39]
    DIRECTION OUTPUT ;
    USE SIGNAL ;
    PORT
      LAYER M5 ;
        RECT  27.12 30.132 27.144 30.216 ;
    END
  END b[39]
  PIN b[3]
    DIRECTION OUTPUT ;
    USE SIGNAL ;
    PORT
      LAYER M5 ;
        RECT  29.808 30.132 29.832 30.216 ;
    END
  END b[3]
  PIN b[40]
    DIRECTION OUTPUT ;
    USE SIGNAL ;
    PORT
      LAYER M5 ;
        RECT  27.216 30.132 27.24 30.216 ;
    END
  END b[40]
  PIN b[41]
    DIRECTION OUTPUT ;
    USE SIGNAL ;
    PORT
      LAYER M5 ;
        RECT  27.312 30.132 27.336 30.216 ;
    END
  END b[41]
  PIN b[42]
    DIRECTION OUTPUT ;
    USE SIGNAL ;
    PORT
      LAYER M5 ;
        RECT  27.408 30.132 27.432 30.216 ;
    END
  END b[42]
  PIN b[43]
    DIRECTION OUTPUT ;
    USE SIGNAL ;
    PORT
      LAYER M5 ;
        RECT  27.504 30.132 27.528 30.216 ;
    END
  END b[43]
  PIN b[44]
    DIRECTION OUTPUT ;
    USE SIGNAL ;
    PORT
      LAYER M5 ;
        RECT  27.6 30.132 27.624 30.216 ;
    END
  END b[44]
  PIN b[45]
    DIRECTION OUTPUT ;
    USE SIGNAL ;
    PORT
      LAYER M5 ;
        RECT  27.696 30.132 27.72 30.216 ;
    END
  END b[45]
  PIN b[46]
    DIRECTION OUTPUT ;
    USE SIGNAL ;
    PORT
      LAYER M5 ;
        RECT  27.792 30.132 27.816 30.216 ;
    END
  END b[46]
  PIN b[47]
    DIRECTION OUTPUT ;
    USE SIGNAL ;
    PORT
      LAYER M5 ;
        RECT  27.888 30.132 27.912 30.216 ;
    END
  END b[47]
  PIN b[48]
    DIRECTION OUTPUT ;
    USE SIGNAL ;
    PORT
      LAYER M5 ;
        RECT  27.984 30.132 28.008 30.216 ;
    END
  END b[48]
  PIN b[49]
    DIRECTION OUTPUT ;
    USE SIGNAL ;
    PORT
      LAYER M5 ;
        RECT  28.08 30.132 28.104 30.216 ;
    END
  END b[49]
  PIN b[4]
    DIRECTION OUTPUT ;
    USE SIGNAL ;
    PORT
      LAYER M5 ;
        RECT  29.904 30.132 29.928 30.216 ;
    END
  END b[4]
  PIN b[50]
    DIRECTION OUTPUT ;
    USE SIGNAL ;
    PORT
      LAYER M5 ;
        RECT  28.176 30.132 28.2 30.216 ;
    END
  END b[50]
  PIN b[51]
    DIRECTION OUTPUT ;
    USE SIGNAL ;
    PORT
      LAYER M5 ;
        RECT  28.272 30.132 28.296 30.216 ;
    END
  END b[51]
  PIN b[52]
    DIRECTION OUTPUT ;
    USE SIGNAL ;
    PORT
      LAYER M5 ;
        RECT  28.368 30.132 28.392 30.216 ;
    END
  END b[52]
  PIN b[53]
    DIRECTION OUTPUT ;
    USE SIGNAL ;
    PORT
      LAYER M5 ;
        RECT  28.464 30.132 28.488 30.216 ;
    END
  END b[53]
  PIN b[54]
    DIRECTION OUTPUT ;
    USE SIGNAL ;
    PORT
      LAYER M5 ;
        RECT  28.56 30.132 28.584 30.216 ;
    END
  END b[54]
  PIN b[55]
    DIRECTION OUTPUT ;
    USE SIGNAL ;
    PORT
      LAYER M5 ;
        RECT  28.656 30.132 28.68 30.216 ;
    END
  END b[55]
  PIN b[56]
    DIRECTION OUTPUT ;
    USE SIGNAL ;
    PORT
      LAYER M5 ;
        RECT  28.752 30.132 28.776 30.216 ;
    END
  END b[56]
  PIN b[57]
    DIRECTION OUTPUT ;
    USE SIGNAL ;
    PORT
      LAYER M5 ;
        RECT  28.848 30.132 28.872 30.216 ;
    END
  END b[57]
  PIN b[58]
    DIRECTION OUTPUT ;
    USE SIGNAL ;
    PORT
      LAYER M5 ;
        RECT  28.944 30.132 28.968 30.216 ;
    END
  END b[58]
  PIN b[59]
    DIRECTION OUTPUT ;
    USE SIGNAL ;
    PORT
      LAYER M5 ;
        RECT  29.04 30.132 29.064 30.216 ;
    END
  END b[59]
  PIN b[5]
    DIRECTION OUTPUT ;
    USE SIGNAL ;
    PORT
      LAYER M5 ;
        RECT  30 30.132 30.024 30.216 ;
    END
  END b[5]
  PIN b[60]
    DIRECTION OUTPUT ;
    USE SIGNAL ;
    PORT
      LAYER M5 ;
        RECT  29.136 30.132 29.16 30.216 ;
    END
  END b[60]
  PIN b[61]
    DIRECTION OUTPUT ;
    USE SIGNAL ;
    PORT
      LAYER M5 ;
        RECT  29.232 30.132 29.256 30.216 ;
    END
  END b[61]
  PIN b[62]
    DIRECTION OUTPUT ;
    USE SIGNAL ;
    PORT
      LAYER M5 ;
        RECT  29.328 30.132 29.352 30.216 ;
    END
  END b[62]
  PIN b[63]
    DIRECTION OUTPUT ;
    USE SIGNAL ;
    PORT
      LAYER M5 ;
        RECT  29.424 30.132 29.448 30.216 ;
    END
  END b[63]
  PIN b[64]
    DIRECTION OUTPUT ;
    USE SIGNAL ;
    PORT
      LAYER M5 ;
        RECT  35.664 30.132 35.688 30.216 ;
    END
  END b[64]
  PIN b[65]
    DIRECTION OUTPUT ;
    USE SIGNAL ;
    PORT
      LAYER M5 ;
        RECT  35.76 30.132 35.784 30.216 ;
    END
  END b[65]
  PIN b[66]
    DIRECTION OUTPUT ;
    USE SIGNAL ;
    PORT
      LAYER M5 ;
        RECT  35.856 30.132 35.88 30.216 ;
    END
  END b[66]
  PIN b[67]
    DIRECTION OUTPUT ;
    USE SIGNAL ;
    PORT
      LAYER M5 ;
        RECT  35.952 30.132 35.976 30.216 ;
    END
  END b[67]
  PIN b[68]
    DIRECTION OUTPUT ;
    USE SIGNAL ;
    PORT
      LAYER M5 ;
        RECT  36.048 30.132 36.072 30.216 ;
    END
  END b[68]
  PIN b[69]
    DIRECTION OUTPUT ;
    USE SIGNAL ;
    PORT
      LAYER M5 ;
        RECT  36.144 30.132 36.168 30.216 ;
    END
  END b[69]
  PIN b[6]
    DIRECTION OUTPUT ;
    USE SIGNAL ;
    PORT
      LAYER M5 ;
        RECT  30.096 30.132 30.12 30.216 ;
    END
  END b[6]
  PIN b[70]
    DIRECTION OUTPUT ;
    USE SIGNAL ;
    PORT
      LAYER M5 ;
        RECT  36.24 30.132 36.264 30.216 ;
    END
  END b[70]
  PIN b[71]
    DIRECTION OUTPUT ;
    USE SIGNAL ;
    PORT
      LAYER M5 ;
        RECT  36.336 30.132 36.36 30.216 ;
    END
  END b[71]
  PIN b[72]
    DIRECTION OUTPUT ;
    USE SIGNAL ;
    PORT
      LAYER M5 ;
        RECT  36.432 30.132 36.456 30.216 ;
    END
  END b[72]
  PIN b[73]
    DIRECTION OUTPUT ;
    USE SIGNAL ;
    PORT
      LAYER M5 ;
        RECT  36.528 30.132 36.552 30.216 ;
    END
  END b[73]
  PIN b[74]
    DIRECTION OUTPUT ;
    USE SIGNAL ;
    PORT
      LAYER M5 ;
        RECT  36.624 30.132 36.648 30.216 ;
    END
  END b[74]
  PIN b[75]
    DIRECTION OUTPUT ;
    USE SIGNAL ;
    PORT
      LAYER M5 ;
        RECT  36.72 30.132 36.744 30.216 ;
    END
  END b[75]
  PIN b[76]
    DIRECTION OUTPUT ;
    USE SIGNAL ;
    PORT
      LAYER M5 ;
        RECT  36.816 30.132 36.84 30.216 ;
    END
  END b[76]
  PIN b[77]
    DIRECTION OUTPUT ;
    USE SIGNAL ;
    PORT
      LAYER M5 ;
        RECT  36.912 30.132 36.936 30.216 ;
    END
  END b[77]
  PIN b[78]
    DIRECTION OUTPUT ;
    USE SIGNAL ;
    PORT
      LAYER M5 ;
        RECT  37.008 30.132 37.032 30.216 ;
    END
  END b[78]
  PIN b[79]
    DIRECTION OUTPUT ;
    USE SIGNAL ;
    PORT
      LAYER M5 ;
        RECT  37.104 30.132 37.128 30.216 ;
    END
  END b[79]
  PIN b[7]
    DIRECTION OUTPUT ;
    USE SIGNAL ;
    PORT
      LAYER M5 ;
        RECT  30.192 30.132 30.216 30.216 ;
    END
  END b[7]
  PIN b[80]
    DIRECTION OUTPUT ;
    USE SIGNAL ;
    PORT
      LAYER M5 ;
        RECT  37.2 30.132 37.224 30.216 ;
    END
  END b[80]
  PIN b[81]
    DIRECTION OUTPUT ;
    USE SIGNAL ;
    PORT
      LAYER M5 ;
        RECT  37.296 30.132 37.32 30.216 ;
    END
  END b[81]
  PIN b[82]
    DIRECTION OUTPUT ;
    USE SIGNAL ;
    PORT
      LAYER M5 ;
        RECT  37.392 30.132 37.416 30.216 ;
    END
  END b[82]
  PIN b[83]
    DIRECTION OUTPUT ;
    USE SIGNAL ;
    PORT
      LAYER M5 ;
        RECT  37.488 30.132 37.512 30.216 ;
    END
  END b[83]
  PIN b[84]
    DIRECTION OUTPUT ;
    USE SIGNAL ;
    PORT
      LAYER M5 ;
        RECT  37.584 30.132 37.608 30.216 ;
    END
  END b[84]
  PIN b[85]
    DIRECTION OUTPUT ;
    USE SIGNAL ;
    PORT
      LAYER M5 ;
        RECT  37.68 30.132 37.704 30.216 ;
    END
  END b[85]
  PIN b[86]
    DIRECTION OUTPUT ;
    USE SIGNAL ;
    PORT
      LAYER M5 ;
        RECT  37.776 30.132 37.8 30.216 ;
    END
  END b[86]
  PIN b[87]
    DIRECTION OUTPUT ;
    USE SIGNAL ;
    PORT
      LAYER M5 ;
        RECT  37.872 30.132 37.896 30.216 ;
    END
  END b[87]
  PIN b[88]
    DIRECTION OUTPUT ;
    USE SIGNAL ;
    PORT
      LAYER M5 ;
        RECT  37.968 30.132 37.992 30.216 ;
    END
  END b[88]
  PIN b[89]
    DIRECTION OUTPUT ;
    USE SIGNAL ;
    PORT
      LAYER M5 ;
        RECT  38.064 30.132 38.088 30.216 ;
    END
  END b[89]
  PIN b[8]
    DIRECTION OUTPUT ;
    USE SIGNAL ;
    PORT
      LAYER M5 ;
        RECT  30.288 30.132 30.312 30.216 ;
    END
  END b[8]
  PIN b[90]
    DIRECTION OUTPUT ;
    USE SIGNAL ;
    PORT
      LAYER M5 ;
        RECT  38.16 30.132 38.184 30.216 ;
    END
  END b[90]
  PIN b[91]
    DIRECTION OUTPUT ;
    USE SIGNAL ;
    PORT
      LAYER M5 ;
        RECT  38.256 30.132 38.28 30.216 ;
    END
  END b[91]
  PIN b[92]
    DIRECTION OUTPUT ;
    USE SIGNAL ;
    PORT
      LAYER M5 ;
        RECT  38.352 30.132 38.376 30.216 ;
    END
  END b[92]
  PIN b[93]
    DIRECTION OUTPUT ;
    USE SIGNAL ;
    PORT
      LAYER M5 ;
        RECT  38.448 30.132 38.472 30.216 ;
    END
  END b[93]
  PIN b[94]
    DIRECTION OUTPUT ;
    USE SIGNAL ;
    PORT
      LAYER M5 ;
        RECT  38.544 30.132 38.568 30.216 ;
    END
  END b[94]
  PIN b[95]
    DIRECTION OUTPUT ;
    USE SIGNAL ;
    PORT
      LAYER M5 ;
        RECT  38.64 30.132 38.664 30.216 ;
    END
  END b[95]
  PIN b[96]
    DIRECTION OUTPUT ;
    USE SIGNAL ;
    PORT
      LAYER M5 ;
        RECT  32.592 30.132 32.616 30.216 ;
    END
  END b[96]
  PIN b[97]
    DIRECTION OUTPUT ;
    USE SIGNAL ;
    PORT
      LAYER M5 ;
        RECT  32.688 30.132 32.712 30.216 ;
    END
  END b[97]
  PIN b[98]
    DIRECTION OUTPUT ;
    USE SIGNAL ;
    PORT
      LAYER M5 ;
        RECT  32.784 30.132 32.808 30.216 ;
    END
  END b[98]
  PIN b[99]
    DIRECTION OUTPUT ;
    USE SIGNAL ;
    PORT
      LAYER M5 ;
        RECT  32.88 30.132 32.904 30.216 ;
    END
  END b[99]
  PIN b[9]
    DIRECTION OUTPUT ;
    USE SIGNAL ;
    PORT
      LAYER M5 ;
        RECT  30.384 30.132 30.408 30.216 ;
    END
  END b[9]
  PIN ck
    DIRECTION INPUT ;
    USE SIGNAL ;
    PORT
      LAYER M4 ;
        RECT  0 14.832 0.084 14.856 ;
    END
  END ck
  PIN ck_o
    DIRECTION OUTPUT ;
    USE SIGNAL ;
    PORT
      LAYER M4 ;
        RECT  0 14.928 0.084 14.952 ;
    END
  END ck_o
  PIN eb
    DIRECTION OUTPUT ;
    USE SIGNAL ;
    PORT
      LAYER M3 ;
        RECT  27.972 30.179 27.99 30.216 ;
    END
  END eb
  PIN en
    DIRECTION INPUT ;
    USE SIGNAL ;
    PORT
      LAYER M4 ;
        RECT  0 15.024 0.084 15.048 ;
    END
  END en
  PIN VDD
    DIRECTION INOUT ;
    USE POWER ;
    PORT
      LAYER M5 ;
        RECT  61.992 2.151 62.112 27.833 ;
        RECT  59.292 2.151 59.412 27.833 ;
        RECT  56.592 2.151 56.712 27.833 ;
        RECT  53.892 2.151 54.012 27.833 ;
        RECT  51.192 2.151 51.312 27.833 ;
        RECT  48.492 2.151 48.612 27.833 ;
        RECT  45.792 2.151 45.912 27.833 ;
        RECT  43.092 2.151 43.212 27.833 ;
        RECT  40.392 2.151 40.512 27.833 ;
        RECT  37.692 2.151 37.812 27.833 ;
        RECT  34.992 2.151 35.112 27.833 ;
        RECT  32.292 2.151 32.412 27.833 ;
        RECT  29.592 2.151 29.712 27.833 ;
        RECT  26.892 2.151 27.012 27.833 ;
        RECT  24.192 2.151 24.312 27.833 ;
        RECT  21.492 2.151 21.612 27.833 ;
        RECT  18.792 2.151 18.912 27.833 ;
        RECT  16.092 2.151 16.212 27.833 ;
        RECT  13.392 2.151 13.512 27.833 ;
        RECT  10.692 2.151 10.812 27.833 ;
        RECT  7.992 2.151 8.112 27.833 ;
        RECT  5.292 2.151 5.412 27.833 ;
        RECT  2.592 2.151 2.712 27.833 ;
    END
  END VDD
  PIN VSS
    DIRECTION INOUT ;
    USE GROUND ;
    PORT
      LAYER M5 ;
        RECT  61.8 2.137 61.92 27.819 ;
        RECT  59.1 2.137 59.22 27.819 ;
        RECT  56.4 2.137 56.52 27.819 ;
        RECT  53.7 2.137 53.82 27.819 ;
        RECT  51 2.137 51.12 27.819 ;
        RECT  48.3 2.137 48.42 27.819 ;
        RECT  45.6 2.137 45.72 27.819 ;
        RECT  42.9 2.137 43.02 27.819 ;
        RECT  40.2 2.137 40.32 27.819 ;
        RECT  37.5 2.137 37.62 27.819 ;
        RECT  34.8 2.137 34.92 27.819 ;
        RECT  32.1 2.137 32.22 27.819 ;
        RECT  29.4 2.137 29.52 27.819 ;
        RECT  26.7 2.137 26.82 27.819 ;
        RECT  24 2.137 24.12 27.819 ;
        RECT  21.3 2.137 21.42 27.819 ;
        RECT  18.6 2.137 18.72 27.819 ;
        RECT  15.9 2.137 16.02 27.819 ;
        RECT  13.2 2.137 13.32 27.819 ;
        RECT  10.5 2.137 10.62 27.819 ;
        RECT  7.8 2.137 7.92 27.819 ;
        RECT  5.1 2.137 5.22 27.819 ;
        RECT  2.4 2.137 2.52 27.819 ;
    END
  END VSS
  OBS
    LAYER RVTN ;
     RECT  2.16 2.16 62.586 2.295 ;
     RECT  2.16 2.565 62.586 2.835 ;
     RECT  2.16 3.105 62.586 3.375 ;
     RECT  2.16 3.645 62.586 3.915 ;
     RECT  2.16 4.185 62.586 4.455 ;
     RECT  2.16 4.725 62.586 4.995 ;
     RECT  2.16 5.265 62.586 5.535 ;
     RECT  2.16 5.805 62.586 6.075 ;
     RECT  2.16 6.345 62.586 6.615 ;
     RECT  2.16 6.885 62.586 7.155 ;
     RECT  2.16 7.425 62.586 7.695 ;
     RECT  2.16 7.965 62.586 8.235 ;
     RECT  2.16 8.505 62.586 8.775 ;
     RECT  2.16 9.045 62.586 9.315 ;
     RECT  2.16 9.585 62.586 9.855 ;
     RECT  2.16 10.125 62.586 10.395 ;
     RECT  2.16 10.665 62.586 10.935 ;
     RECT  2.16 11.205 62.586 11.475 ;
     RECT  2.16 11.745 62.586 12.015 ;
     RECT  2.16 12.285 62.586 12.555 ;
     RECT  2.16 12.825 62.586 13.095 ;
     RECT  2.16 13.365 62.586 13.635 ;
     RECT  2.16 13.905 62.586 14.175 ;
     RECT  2.16 14.445 62.586 14.715 ;
     RECT  2.16 14.985 62.586 15.255 ;
     RECT  2.16 15.525 62.586 15.795 ;
     RECT  2.16 16.065 62.586 16.335 ;
     RECT  2.16 16.605 62.586 16.875 ;
     RECT  2.16 17.145 62.586 17.415 ;
     RECT  2.16 17.685 62.586 17.955 ;
     RECT  2.16 18.225 62.586 18.495 ;
     RECT  2.16 18.765 62.586 19.035 ;
     RECT  2.16 19.305 62.586 19.575 ;
     RECT  2.16 19.845 62.586 20.115 ;
     RECT  2.16 20.385 62.586 20.655 ;
     RECT  2.16 20.925 62.586 21.195 ;
     RECT  2.16 21.465 62.586 21.735 ;
     RECT  2.16 22.005 62.586 22.275 ;
     RECT  2.16 22.545 62.586 22.815 ;
     RECT  2.16 23.085 62.586 23.355 ;
     RECT  2.16 23.625 62.586 23.895 ;
     RECT  2.16 24.165 62.586 24.435 ;
     RECT  2.16 24.705 62.586 24.975 ;
     RECT  2.16 25.245 62.586 25.515 ;
     RECT  2.16 25.785 62.586 26.055 ;
     RECT  2.16 26.325 62.586 26.595 ;
     RECT  2.16 26.865 62.586 27.135 ;
     RECT  2.16 27.405 62.586 27.675 ;
    LAYER RVTP ;
     RECT  2.16 2.295 62.586 2.565 ;
     RECT  2.16 2.835 62.586 3.105 ;
     RECT  2.16 3.375 62.586 3.645 ;
     RECT  2.16 3.915 62.586 4.185 ;
     RECT  2.16 4.455 62.586 4.725 ;
     RECT  2.16 4.995 62.586 5.265 ;
     RECT  2.16 5.535 62.586 5.805 ;
     RECT  2.16 6.075 62.586 6.345 ;
     RECT  2.16 6.615 62.586 6.885 ;
     RECT  2.16 7.155 62.586 7.425 ;
     RECT  2.16 7.695 62.586 7.965 ;
     RECT  2.16 8.235 62.586 8.505 ;
     RECT  2.16 8.775 62.586 9.045 ;
     RECT  2.16 9.315 62.586 9.585 ;
     RECT  2.16 9.855 62.586 10.125 ;
     RECT  2.16 10.395 62.586 10.665 ;
     RECT  2.16 10.935 62.586 11.205 ;
     RECT  2.16 11.475 62.586 11.745 ;
     RECT  2.16 12.015 62.586 12.285 ;
     RECT  2.16 12.555 62.586 12.825 ;
     RECT  2.16 13.095 62.586 13.365 ;
     RECT  2.16 13.635 62.586 13.905 ;
     RECT  2.16 14.175 62.586 14.445 ;
     RECT  2.16 14.715 62.586 14.985 ;
     RECT  2.16 15.255 62.586 15.525 ;
     RECT  2.16 15.795 62.586 16.065 ;
     RECT  2.16 16.335 62.586 16.605 ;
     RECT  2.16 16.875 62.586 17.145 ;
     RECT  2.16 17.415 62.586 17.685 ;
     RECT  2.16 17.955 62.586 18.225 ;
     RECT  2.16 18.495 62.586 18.765 ;
     RECT  2.16 19.035 62.586 19.305 ;
     RECT  2.16 19.575 62.586 19.845 ;
     RECT  2.16 20.115 62.586 20.385 ;
     RECT  2.16 20.655 62.586 20.925 ;
     RECT  2.16 21.195 62.586 21.465 ;
     RECT  2.16 21.735 62.586 22.005 ;
     RECT  2.16 22.275 62.586 22.545 ;
     RECT  2.16 22.815 62.586 23.085 ;
     RECT  2.16 23.355 62.586 23.625 ;
     RECT  2.16 23.895 62.586 24.165 ;
     RECT  2.16 24.435 62.586 24.705 ;
     RECT  2.16 24.975 62.586 25.245 ;
     RECT  2.16 25.515 62.586 25.785 ;
     RECT  2.16 26.055 62.586 26.325 ;
     RECT  2.16 26.595 62.586 26.865 ;
     RECT  2.16 27.135 62.586 27.405 ;
     RECT  2.16 27.675 62.586 27.81 ;
    LAYER M1 ;
     RECT  2.16 2.151 62.586 27.819 ;
    LAYER M2 ;
     RECT  2.16 2.151 32.611 27.819 ;
     RECT  32.611 2.151 33.647 27.864 ;
     RECT  33.647 2.151 62.586 27.819 ;
     RECT  62.586 6.822 62.843 19.098 ;
     RECT  62.843 6.822 63.311 14.976 ;
     RECT  62.843 15.768 63.311 19.098 ;
     RECT  63.311 9.864 63.779 14.976 ;
     RECT  63.311 6.822 63.887 7.686 ;
     RECT  63.311 8.55 63.887 8.874 ;
     RECT  63.779 9.864 63.887 14.814 ;
     RECT  63.311 16.38 63.887 17.676 ;
     RECT  63.311 18.846 63.887 19.062 ;
     RECT  63.887 6.93 63.923 7.524 ;
     RECT  63.887 8.55 63.923 8.838 ;
     RECT  63.887 9.9 63.923 10.854 ;
     RECT  63.887 11.79 63.923 11.808 ;
     RECT  63.887 13.374 63.923 13.392 ;
     RECT  63.887 14.49 63.923 14.508 ;
     RECT  63.887 16.578 63.923 17.514 ;
     RECT  63.923 6.93 63.959 6.948 ;
     RECT  63.923 8.82 63.959 8.838 ;
     RECT  63.923 9.9 63.959 10.044 ;
     RECT  63.923 16.578 63.959 16.866 ;
     RECT  63.959 10.026 63.995 10.044 ;
     RECT  64.651 7.506 64.751 7.524 ;
     RECT  64.651 10.206 64.751 10.224 ;
     RECT  64.651 15.876 64.751 15.894 ;
    LAYER M3 ;
     RECT  2.415 2.143 2.505 2.413 ;
     RECT  5.115 2.143 5.205 2.413 ;
     RECT  7.815 2.143 7.905 2.413 ;
     RECT  10.515 2.143 10.605 2.413 ;
     RECT  13.215 2.143 13.305 2.413 ;
     RECT  15.915 2.143 16.005 2.413 ;
     RECT  18.615 2.143 18.705 2.413 ;
     RECT  21.315 2.143 21.405 2.413 ;
     RECT  24.015 2.143 24.105 2.413 ;
     RECT  26.715 2.143 26.805 2.413 ;
     RECT  29.415 2.143 29.505 2.413 ;
     RECT  32.115 2.143 32.205 2.413 ;
     RECT  34.815 2.143 34.905 2.413 ;
     RECT  37.515 2.143 37.605 2.413 ;
     RECT  40.215 2.143 40.305 2.413 ;
     RECT  42.915 2.143 43.005 2.413 ;
     RECT  45.615 2.143 45.705 2.413 ;
     RECT  48.315 2.143 48.405 2.413 ;
     RECT  51.015 2.143 51.105 2.413 ;
     RECT  53.715 2.143 53.805 2.413 ;
     RECT  56.415 2.143 56.505 2.413 ;
     RECT  59.115 2.143 59.205 2.413 ;
     RECT  61.815 2.143 61.905 2.413 ;
     RECT  59.115 2.413 59.397 6.655 ;
     RECT  58.14 6.655 58.158 6.691 ;
     RECT  61.815 2.413 62.097 6.691 ;
     RECT  58.14 6.691 58.266 6.781 ;
     RECT  58.14 6.781 58.374 6.853 ;
     RECT  59.115 6.655 60.102 6.853 ;
     RECT  61.815 6.691 62.154 6.853 ;
     RECT  58.032 6.853 58.374 6.889 ;
     RECT  59.115 6.853 60.318 6.889 ;
     RECT  56.415 2.413 56.697 6.925 ;
     RECT  58.032 6.889 60.318 6.925 ;
     RECT  61.704 6.853 62.154 6.925 ;
     RECT  63.864 6.817 63.882 6.925 ;
     RECT  54.72 6.889 54.738 6.961 ;
     RECT  33.624 6.853 33.642 7.123 ;
     RECT  63.864 6.925 63.954 7.181 ;
     RECT  56.415 6.925 57.222 7.195 ;
     RECT  58.032 6.925 62.154 7.195 ;
     RECT  33.624 7.123 34.074 7.231 ;
     RECT  54.72 6.961 54.882 7.231 ;
     RECT  56.415 7.195 62.154 7.243 ;
     RECT  48.315 2.413 48.597 7.321 ;
     RECT  54.72 7.231 55.458 7.321 ;
     RECT  56.415 7.243 62.73 7.321 ;
     RECT  64.728 7.483 64.746 7.501 ;
     RECT  64.656 7.501 64.746 7.529 ;
     RECT  64.656 7.529 64.674 7.565 ;
     RECT  47.016 7.501 47.034 7.619 ;
     RECT  52.092 7.465 52.11 7.619 ;
     RECT  54.72 7.321 62.73 7.619 ;
     RECT  51.015 2.413 51.297 7.627 ;
     RECT  60.228 7.619 62.73 7.723 ;
     RECT  63.864 7.181 63.918 7.723 ;
     RECT  32.115 2.413 32.397 7.771 ;
     RECT  33.12 7.231 34.074 7.771 ;
     RECT  50.724 7.627 51.297 7.799 ;
     RECT  34.815 2.413 35.097 8.005 ;
     RECT  32.115 7.771 34.074 8.041 ;
     RECT  34.815 8.005 35.406 8.041 ;
     RECT  32.115 8.041 35.406 8.131 ;
     RECT  54.72 7.619 59.454 8.159 ;
     RECT  60.228 7.723 63.918 8.395 ;
     RECT  54.792 8.159 59.454 8.525 ;
     RECT  55.836 8.525 59.454 8.537 ;
     RECT  55.98 8.537 59.454 8.539 ;
     RECT  60.192 8.395 63.954 8.539 ;
     RECT  32.115 8.131 35.442 8.573 ;
     RECT  33.3 8.573 35.442 8.671 ;
     RECT  33.3 8.671 35.766 8.707 ;
     RECT  36.504 8.581 36.522 8.707 ;
     RECT  54.792 8.525 54.81 8.771 ;
     RECT  50.796 7.799 51.297 8.843 ;
     RECT  55.98 8.539 63.954 8.843 ;
     RECT  37.515 2.413 37.797 8.851 ;
     RECT  33.3 8.707 36.522 8.969 ;
     RECT  55.98 8.843 63.918 9.101 ;
     RECT  53.715 2.413 53.997 9.211 ;
     RECT  37.332 8.851 37.797 9.391 ;
     RECT  37.296 9.391 37.797 9.509 ;
     RECT  58.284 9.101 63.918 9.643 ;
     RECT  55.98 9.101 57.186 9.661 ;
     RECT  38.808 9.787 38.826 9.823 ;
     RECT  58.284 9.643 63.954 9.835 ;
     RECT  53.715 9.211 54.162 9.851 ;
     RECT  33.3 8.969 36.486 9.859 ;
     RECT  38.664 9.823 38.826 9.859 ;
     RECT  38.664 9.859 38.898 9.959 ;
     RECT  38.736 9.959 38.754 10.049 ;
     RECT  55.872 9.661 57.186 10.049 ;
     RECT  58.284 9.835 63.99 10.049 ;
     RECT  54.72 9.859 54.738 10.165 ;
     RECT  56.412 10.049 57.186 10.165 ;
     RECT  56.412 10.165 57.258 10.201 ;
     RECT  58.284 10.049 63.918 10.201 ;
     RECT  64.728 10.171 64.746 10.201 ;
     RECT  64.656 10.201 64.746 10.229 ;
     RECT  64.656 10.229 64.674 10.253 ;
     RECT  54.72 10.165 55.458 10.493 ;
     RECT  30.564 10.561 30.582 10.705 ;
     RECT  31.356 10.561 31.374 10.705 ;
     RECT  33.3 9.859 36.774 10.733 ;
     RECT  30.564 10.705 31.374 10.831 ;
     RECT  37.515 9.509 37.797 10.831 ;
     RECT  56.412 10.201 63.918 10.867 ;
     RECT  51.015 8.843 51.297 11.137 ;
     RECT  33.3 10.733 35.91 11.165 ;
     RECT  50.724 11.137 51.297 11.273 ;
     RECT  29.415 2.413 29.697 11.281 ;
     RECT  30.456 10.831 31.374 11.281 ;
     RECT  54.72 10.493 55.422 11.281 ;
     RECT  56.16 10.867 63.918 11.281 ;
     RECT  54.72 11.281 63.918 11.357 ;
     RECT  33.3 11.165 35.874 11.405 ;
     RECT  29.415 11.281 31.374 11.479 ;
     RECT  32.115 8.573 32.397 11.479 ;
     RECT  29.415 11.479 32.397 11.515 ;
     RECT  33.3 11.405 35.73 11.515 ;
     RECT  54.72 11.357 54.918 11.549 ;
     RECT  54.72 11.549 54.882 11.579 ;
     RECT  55.692 11.357 63.918 11.741 ;
     RECT  63.864 11.741 63.918 11.813 ;
     RECT  55.692 11.741 62.766 11.975 ;
     RECT  55.692 11.975 62.73 11.981 ;
     RECT  36.756 10.733 36.774 12.289 ;
     RECT  54.756 11.579 54.882 12.325 ;
     RECT  51.015 11.273 51.297 12.571 ;
     RECT  63.864 11.813 63.882 12.811 ;
     RECT  36.54 12.289 36.774 12.829 ;
     RECT  52.74 12.721 52.758 12.845 ;
     RECT  53.715 9.851 53.997 12.865 ;
     RECT  54.72 12.325 54.882 12.865 ;
     RECT  55.728 11.981 62.73 12.907 ;
     RECT  63.864 12.811 63.918 12.907 ;
     RECT  29.415 11.515 35.73 12.991 ;
     RECT  36.504 12.829 36.774 12.991 ;
     RECT  45.615 2.413 45.897 12.991 ;
     RECT  48.315 7.321 49.302 12.991 ;
     RECT  45.324 12.991 46.206 13.037 ;
     RECT  48.204 12.991 49.302 13.037 ;
     RECT  50.724 12.571 51.297 13.037 ;
     RECT  53.715 12.865 54.882 13.199 ;
     RECT  54.72 13.199 54.882 13.274 ;
     RECT  55.728 12.907 63.918 13.274 ;
     RECT  54.72 13.274 63.918 13.397 ;
     RECT  29.415 12.991 36.774 13.405 ;
     RECT  37.515 10.831 38.358 13.405 ;
     RECT  2.415 2.413 2.697 13.531 ;
     RECT  45.324 13.037 46.17 13.595 ;
     RECT  54.72 13.397 63.882 13.595 ;
     RECT  45.324 13.595 45.99 13.613 ;
     RECT  2.34 13.531 2.697 13.661 ;
     RECT  29.415 13.405 38.358 13.801 ;
     RECT  40.215 2.413 40.497 13.801 ;
     RECT  55.584 13.595 63.882 13.907 ;
     RECT  55.584 13.907 62.766 13.949 ;
     RECT  55.944 13.949 62.766 13.997 ;
     RECT  2.415 13.661 2.697 14.107 ;
     RECT  45.615 13.613 45.99 14.141 ;
     RECT  54.72 13.595 54.846 14.171 ;
     RECT  55.944 13.997 62.73 14.171 ;
     RECT  56.088 14.171 62.73 14.189 ;
     RECT  2.415 14.107 2.826 14.203 ;
     RECT  56.124 14.189 62.73 14.207 ;
     RECT  54.756 14.171 54.846 14.243 ;
     RECT  2.415 14.203 3.546 14.251 ;
     RECT  63.864 13.907 63.882 14.443 ;
     RECT  63.864 14.443 63.918 14.513 ;
     RECT  2.415 14.251 3.942 14.521 ;
     RECT  2.415 14.521 4.05 14.611 ;
     RECT  63.864 14.513 63.882 14.635 ;
     RECT  2.415 14.611 4.158 14.669 ;
     RECT  2.415 14.669 4.05 14.675 ;
     RECT  63.756 14.635 63.882 14.819 ;
     RECT  2.415 14.675 3.654 14.827 ;
     RECT  56.376 14.207 62.73 14.827 ;
     RECT  56.376 14.827 62.766 14.923 ;
     RECT  2.304 14.827 3.654 14.945 ;
     RECT  54.756 14.243 54.81 14.953 ;
     RECT  56.376 14.923 62.838 14.953 ;
     RECT  63.756 14.819 63.774 14.981 ;
     RECT  2.304 14.945 3.618 15.019 ;
     RECT  54.72 14.953 54.81 15.025 ;
     RECT  56.34 14.953 62.838 15.025 ;
     RECT  2.196 15.019 3.618 15.179 ;
     RECT  15.915 2.413 16.197 15.187 ;
     RECT  42.915 2.413 43.197 15.187 ;
     RECT  56.196 15.025 62.838 15.295 ;
     RECT  55.98 15.295 62.838 15.355 ;
     RECT  6.804 15.187 6.822 15.359 ;
     RECT  55.764 15.355 62.838 15.403 ;
     RECT  54.72 15.025 54.846 15.499 ;
     RECT  42.66 15.187 43.197 15.719 ;
     RECT  54.72 15.499 54.99 15.727 ;
     RECT  55.764 15.403 63.306 15.727 ;
     RECT  2.196 15.179 3.438 15.791 ;
     RECT  54.72 15.727 63.306 15.791 ;
     RECT  64.728 15.835 64.746 15.871 ;
     RECT  64.656 15.871 64.746 15.899 ;
     RECT  64.656 15.899 64.674 15.917 ;
     RECT  29.415 13.801 40.497 15.961 ;
     RECT  2.304 15.791 3.438 15.979 ;
     RECT  2.304 15.979 3.546 16.025 ;
     RECT  26.715 2.413 26.997 16.033 ;
     RECT  42.768 15.719 43.197 16.061 ;
     RECT  56.232 15.791 63.306 16.075 ;
     RECT  29.415 15.961 40.986 16.105 ;
     RECT  56.232 16.075 63.882 16.169 ;
     RECT  63.864 16.169 63.882 16.171 ;
     RECT  29.415 16.105 41.202 16.231 ;
     RECT  2.304 16.025 2.826 16.259 ;
     RECT  26.715 16.033 27.594 16.267 ;
     RECT  2.304 16.259 2.697 16.295 ;
     RECT  26.715 16.267 27.738 16.375 ;
     RECT  51.015 13.037 51.297 16.375 ;
     RECT  26.715 16.375 28.458 16.411 ;
     RECT  29.415 16.231 41.274 16.411 ;
     RECT  42.804 16.061 43.197 16.439 ;
     RECT  54.72 15.791 55.494 16.445 ;
     RECT  50.724 16.375 51.297 16.529 ;
     RECT  63.864 16.171 63.918 16.555 ;
     RECT  26.715 16.411 41.274 16.601 ;
     RECT  26.715 16.601 41.022 16.771 ;
     RECT  48.315 13.037 49.302 16.771 ;
     RECT  47.88 16.771 49.302 16.829 ;
     RECT  63.864 16.555 63.954 16.871 ;
     RECT  47.952 16.829 49.302 16.877 ;
     RECT  48.312 16.877 49.302 17.069 ;
     RECT  56.232 16.169 62.802 17.185 ;
     RECT  56.016 17.185 62.802 17.227 ;
     RECT  63.864 16.871 63.918 17.227 ;
     RECT  26.604 16.771 41.022 17.419 ;
     RECT  56.016 17.227 63.918 17.549 ;
     RECT  54.72 16.445 54.918 17.581 ;
     RECT  56.016 17.549 63.882 17.581 ;
     RECT  26.532 17.419 41.022 17.645 ;
     RECT  54.72 17.581 63.882 17.681 ;
     RECT  51.015 16.529 51.297 17.689 ;
     RECT  26.568 17.645 41.022 17.693 ;
     RECT  50.724 17.689 51.297 17.915 ;
     RECT  39.672 17.693 41.022 17.933 ;
     RECT  54.72 17.681 63.306 18.149 ;
     RECT  55.188 18.149 63.306 18.269 ;
     RECT  26.568 17.693 38.754 18.317 ;
     RECT  56.16 18.269 63.306 18.761 ;
     RECT  47.088 7.771 47.106 18.763 ;
     RECT  48.315 17.069 49.302 18.763 ;
     RECT  63.288 18.761 63.306 18.763 ;
     RECT  26.568 18.317 38.646 18.797 ;
     RECT  55.188 18.269 55.206 18.797 ;
     RECT  47.088 18.763 49.302 18.959 ;
     RECT  56.16 18.761 62.154 18.959 ;
     RECT  58.032 18.959 62.154 18.995 ;
     RECT  63.288 18.763 63.882 19.067 ;
     RECT  58.428 18.995 62.154 19.085 ;
     RECT  63.288 19.067 63.306 19.103 ;
     RECT  54.72 19.201 54.882 19.301 ;
     RECT  54.72 19.301 54.81 19.373 ;
     RECT  56.16 18.959 57.294 19.387 ;
     RECT  56.088 19.387 57.294 19.535 ;
     RECT  54.72 19.373 54.738 19.769 ;
     RECT  28.332 18.797 38.646 19.949 ;
     RECT  39.672 17.933 40.497 20.525 ;
     RECT  45.615 14.141 45.897 21.067 ;
     RECT  26.568 18.797 27.054 21.091 ;
     RECT  28.872 19.949 38.646 21.101 ;
     RECT  45.396 21.067 45.897 21.115 ;
     RECT  15.732 15.187 16.197 21.155 ;
     RECT  42.915 16.439 43.197 21.361 ;
     RECT  47.088 18.959 47.106 21.389 ;
     RECT  45.396 21.115 46.062 21.659 ;
     RECT  58.428 19.085 62.097 22.541 ;
     RECT  26.568 21.091 27.09 22.795 ;
     RECT  41.292 22.513 41.31 23.053 ;
     RECT  61.2 22.541 62.097 23.081 ;
     RECT  26.568 22.795 27.342 23.165 ;
     RECT  45.615 21.659 45.897 23.629 ;
     RECT  56.415 19.535 57.294 23.657 ;
     RECT  26.568 23.165 27.306 24.523 ;
     RECT  61.272 23.081 62.097 24.809 ;
     RECT  33.3 21.101 38.646 25.085 ;
     RECT  26.568 24.523 27.342 25.661 ;
     RECT  33.3 25.085 36.054 25.861 ;
     RECT  37.008 25.085 38.646 25.861 ;
     RECT  41.292 23.053 41.634 25.889 ;
     RECT  58.428 22.541 60.318 26.555 ;
     RECT  26.715 25.661 27.342 26.671 ;
     RECT  28.872 21.101 32.49 26.671 ;
     RECT  26.715 26.671 32.49 26.789 ;
     RECT  33.3 25.861 38.646 26.933 ;
     RECT  33.3 26.933 35.73 27.031 ;
     RECT  59.115 26.555 60.318 27.131 ;
     RECT  47.34 21.937 47.358 27.163 ;
     RECT  46.764 27.163 47.358 27.211 ;
     RECT  46.764 27.211 47.466 27.239 ;
     RECT  47.34 27.239 47.466 27.329 ;
     RECT  59.115 27.131 60.03 27.329 ;
     RECT  28.872 26.789 32.49 27.341 ;
     RECT  33.228 27.031 35.73 27.365 ;
     RECT  41.292 25.889 41.31 27.365 ;
     RECT  47.34 27.329 47.358 27.365 ;
     RECT  37.008 26.933 38.646 27.473 ;
     RECT  48.315 18.959 49.302 27.473 ;
     RECT  42.444 21.361 43.197 27.509 ;
     RECT  2.415 16.295 2.697 27.557 ;
     RECT  5.115 2.413 5.397 27.557 ;
     RECT  7.815 2.413 8.097 27.557 ;
     RECT  10.515 2.413 10.797 27.557 ;
     RECT  13.215 2.413 13.497 27.557 ;
     RECT  15.915 21.155 16.197 27.557 ;
     RECT  18.615 2.413 18.897 27.557 ;
     RECT  21.315 2.413 21.597 27.557 ;
     RECT  24.015 2.413 24.297 27.557 ;
     RECT  26.715 26.789 28.062 27.557 ;
     RECT  40.215 20.525 40.497 27.557 ;
     RECT  48.315 27.473 48.597 27.557 ;
     RECT  51.015 17.915 51.297 27.557 ;
     RECT  53.715 13.199 53.997 27.557 ;
     RECT  56.415 23.657 56.697 27.557 ;
     RECT  59.115 27.329 59.397 27.557 ;
     RECT  61.815 24.809 62.097 27.557 ;
     RECT  26.907 27.557 28.062 27.635 ;
     RECT  45 23.629 45.897 27.635 ;
     RECT  42.768 27.509 43.197 27.743 ;
     RECT  29.016 27.341 32.49 27.751 ;
     RECT  33.228 27.365 33.642 27.751 ;
     RECT  38.592 27.473 38.646 27.751 ;
     RECT  2.607 27.557 2.697 27.827 ;
     RECT  5.307 27.557 5.397 27.827 ;
     RECT  8.007 27.557 8.097 27.827 ;
     RECT  10.707 27.557 10.797 27.827 ;
     RECT  13.407 27.557 13.497 27.827 ;
     RECT  16.107 27.557 16.197 27.827 ;
     RECT  18.807 27.557 18.897 27.827 ;
     RECT  21.507 27.557 21.597 27.827 ;
     RECT  24.207 27.557 24.297 27.827 ;
     RECT  26.907 27.635 27.99 27.827 ;
     RECT  29.016 27.751 33.642 27.827 ;
     RECT  37.008 27.473 37.797 27.827 ;
     RECT  40.407 27.557 40.497 27.827 ;
     RECT  43.107 27.743 43.197 27.827 ;
     RECT  45.144 27.635 45.897 27.827 ;
     RECT  48.507 27.557 48.597 27.827 ;
     RECT  51.207 27.557 51.297 27.827 ;
     RECT  53.907 27.557 53.997 27.827 ;
     RECT  56.607 27.557 56.697 27.827 ;
     RECT  59.307 27.557 59.397 27.827 ;
     RECT  62.007 27.557 62.097 27.827 ;
     RECT  30.024 27.827 33.642 27.869 ;
     RECT  38.592 27.751 38.79 27.917 ;
     RECT  30.024 27.869 33.606 28.061 ;
     RECT  32.076 28.061 33.606 28.205 ;
     RECT  38.592 27.917 38.646 28.397 ;
     RECT  32.436 28.205 33.606 28.445 ;
     RECT  29.016 27.827 29.034 28.493 ;
     RECT  30.024 28.061 31.266 28.493 ;
     RECT  32.436 28.445 33.534 28.493 ;
     RECT  37.008 27.827 37.674 28.493 ;
     RECT  38.628 28.397 38.646 28.493 ;
     RECT  37.656 28.493 37.674 28.541 ;
     RECT  30.024 28.493 30.654 29.069 ;
     RECT  33.3 28.493 33.462 29.069 ;
     RECT  30.06 29.069 30.078 29.645 ;
     RECT  34.38 27.365 35.73 29.645 ;
     RECT  31.068 29.755 31.086 29.851 ;
     RECT  31.068 29.851 31.266 29.947 ;
     RECT  29.232 29.995 29.25 30.043 ;
     RECT  27.324 27.827 27.99 30.125 ;
     RECT  29.232 30.043 29.646 30.125 ;
     RECT  30.924 29.947 31.266 30.125 ;
     RECT  33.3 29.069 33.318 30.125 ;
     RECT  34.38 29.645 35.334 30.125 ;
     RECT  29.628 30.125 29.646 30.173 ;
     RECT  45.144 27.827 45.162 30.173 ;
     RECT  27.972 30.125 27.99 30.204 ;
    LAYER M4 ;
     RECT  0.06 14.832 0.133 15.048 ;
     RECT  0.133 14.64 2.293 15.048 ;
     RECT  2.293 14.64 2.401 15.576 ;
     RECT  2.329 13.632 2.408 13.656 ;
     RECT  2.401 14.64 2.408 16.056 ;
     RECT  2.408 2.148 2.512 27.552 ;
     RECT  2.512 2.418 2.6 27.552 ;
     RECT  2.6 2.418 2.704 27.822 ;
     RECT  2.704 13.632 3.155 16.056 ;
     RECT  3.155 13.632 3.449 16.008 ;
     RECT  3.449 15.984 3.601 16.008 ;
     RECT  3.449 13.632 3.925 14.664 ;
     RECT  3.925 13.584 5.108 14.664 ;
     RECT  5.108 2.148 5.212 27.552 ;
     RECT  5.212 2.418 5.3 27.552 ;
     RECT  5.3 2.418 5.404 27.822 ;
     RECT  5.404 13.584 7.808 13.896 ;
     RECT  7.808 2.148 7.912 27.552 ;
     RECT  7.912 2.418 8 27.552 ;
     RECT  8 2.418 8.104 27.822 ;
     RECT  8.104 13.584 10.508 13.896 ;
     RECT  10.508 2.148 10.612 27.552 ;
     RECT  10.612 2.418 10.7 27.552 ;
     RECT  10.7 2.418 10.804 27.822 ;
     RECT  10.804 13.584 13.208 13.896 ;
     RECT  13.208 2.148 13.312 27.552 ;
     RECT  13.312 2.418 13.4 27.552 ;
     RECT  13.4 2.418 13.504 27.822 ;
     RECT  13.504 13.584 15.908 13.896 ;
     RECT  15.908 2.148 16.012 27.552 ;
     RECT  16.012 2.418 16.1 27.552 ;
     RECT  16.1 2.418 16.204 27.822 ;
     RECT  16.204 13.584 18.608 13.896 ;
     RECT  18.608 2.148 18.712 27.552 ;
     RECT  18.712 2.418 18.8 27.552 ;
     RECT  18.8 2.418 18.904 27.822 ;
     RECT  18.904 13.584 21.308 13.896 ;
     RECT  21.308 2.148 21.412 27.552 ;
     RECT  21.412 2.418 21.5 27.552 ;
     RECT  21.5 2.418 21.604 27.822 ;
     RECT  21.604 13.584 24.008 13.896 ;
     RECT  24.008 2.148 24.112 27.552 ;
     RECT  24.112 2.418 24.2 27.552 ;
     RECT  24.2 2.418 24.304 27.822 ;
     RECT  26.437 25.056 26.485 25.08 ;
     RECT  26.485 25.056 26.513 25.56 ;
     RECT  26.485 30.048 26.581 30.072 ;
     RECT  24.304 13.584 26.708 13.896 ;
     RECT  26.581 19.872 26.708 19.896 ;
     RECT  26.513 25.056 26.708 25.656 ;
     RECT  26.708 2.148 26.812 27.552 ;
     RECT  26.581 29.952 26.821 30.072 ;
     RECT  26.812 2.418 26.9 27.552 ;
     RECT  26.821 29.808 26.917 30.072 ;
     RECT  26.9 2.418 27.004 27.822 ;
     RECT  27.004 24.528 27.203 24.648 ;
     RECT  26.917 29.712 27.251 30.072 ;
     RECT  27.251 29.856 27.269 30.072 ;
     RECT  27.269 29.856 27.299 30.12 ;
     RECT  27.299 29.952 27.347 30.12 ;
     RECT  27.203 24.528 27.353 24.552 ;
     RECT  27.347 30.096 27.353 30.12 ;
     RECT  27.004 22.512 27.388 23.16 ;
     RECT  27.388 22.512 27.923 22.632 ;
     RECT  27.004 17.472 27.929 18.792 ;
     RECT  27.929 18.048 27.973 18.792 ;
     RECT  27.004 19.92 27.973 19.944 ;
     RECT  27.973 18.048 28.549 19.944 ;
     RECT  27.004 26.64 28.817 26.808 ;
     RECT  28.741 28.464 29.045 28.488 ;
     RECT  28.549 18.048 29.125 20.52 ;
     RECT  29.125 18.048 29.173 20.616 ;
     RECT  29.077 29.952 29.173 29.976 ;
     RECT  29.173 29.952 29.221 30.024 ;
     RECT  29.173 18.048 29.269 20.904 ;
     RECT  29.221 29.904 29.269 30.12 ;
     RECT  27.004 13.584 29.408 13.896 ;
     RECT  27.004 16.272 29.408 16.296 ;
     RECT  29.269 18.048 29.408 21 ;
     RECT  28.817 26.64 29.408 27.336 ;
     RECT  29.408 2.148 29.512 27.96 ;
     RECT  29.269 29.808 29.617 30.12 ;
     RECT  29.617 29.808 29.701 30.168 ;
     RECT  29.512 2.418 29.704 27.96 ;
     RECT  29.704 19.248 29.765 19.272 ;
     RECT  29.701 29.616 29.969 30.168 ;
     RECT  29.704 20.592 29.981 21 ;
     RECT  29.981 20.592 30.053 20.904 ;
     RECT  29.704 26.64 30.373 27.96 ;
     RECT  29.969 29.04 30.373 30.168 ;
     RECT  30.373 26.64 30.665 30.168 ;
     RECT  29.704 16.272 30.697 16.296 ;
     RECT  29.704 13.584 30.757 13.896 ;
     RECT  30.697 16.128 30.769 16.296 ;
     RECT  29.704 10.992 30.773 12.6 ;
     RECT  30.773 11.856 30.853 12.6 ;
     RECT  30.757 13.584 30.853 14.856 ;
     RECT  30.053 20.88 30.881 20.904 ;
     RECT  30.853 11.856 30.899 14.856 ;
     RECT  30.757 18.768 30.899 18.888 ;
     RECT  30.757 22.704 30.899 22.824 ;
     RECT  30.899 11.856 30.917 14.808 ;
     RECT  30.917 12.384 31.025 14.808 ;
     RECT  30.665 26.64 31.045 28.488 ;
     RECT  30.665 29.76 31.187 30.168 ;
     RECT  31.187 29.856 31.277 30.168 ;
     RECT  31.277 30 31.283 30.168 ;
     RECT  30.769 16.032 31.309 16.296 ;
     RECT  30.949 17.424 31.309 17.448 ;
     RECT  31.283 30.096 31.321 30.168 ;
     RECT  31.025 13.104 32.108 14.808 ;
     RECT  31.309 16.032 32.108 17.448 ;
     RECT  31.909 20.304 32.108 20.424 ;
     RECT  31.045 26.592 32.108 28.488 ;
     RECT  32.108 2.148 32.212 28.488 ;
     RECT  32.212 2.418 32.404 28.488 ;
     RECT  32.404 20.352 32.717 21.096 ;
     RECT  32.717 20.352 33.005 20.376 ;
     RECT  32.404 7.968 33.077 8.568 ;
     RECT  33.077 7.968 33.149 7.992 ;
     RECT  31.321 30.144 33.157 30.168 ;
     RECT  32.404 26.592 33.349 28.488 ;
     RECT  33.349 26.592 33.473 29.064 ;
     RECT  32.404 11.376 33.541 11.4 ;
     RECT  33.473 26.592 33.545 28.488 ;
     RECT  33.545 26.592 33.617 28.44 ;
     RECT  32.404 13.584 33.829 13.896 ;
     RECT  33.829 13.056 34.021 13.896 ;
     RECT  34.021 13.056 34.117 14.232 ;
     RECT  33.541 11.376 34.501 11.976 ;
     RECT  34.501 11.232 34.597 11.976 ;
     RECT  34.117 13.008 34.597 14.232 ;
     RECT  34.597 11.232 34.652 14.232 ;
     RECT  33.617 26.592 34.765 27.672 ;
     RECT  34.405 9.792 34.808 9.816 ;
     RECT  34.652 10.848 34.808 14.232 ;
     RECT  32.404 16.032 34.808 17.448 ;
     RECT  34.765 26.592 34.808 27.912 ;
     RECT  33.157 30.096 34.885 30.168 ;
     RECT  34.808 2.148 34.912 27.912 ;
     RECT  34.885 30.048 34.981 30.168 ;
     RECT  34.981 30 35.077 30.168 ;
     RECT  34.912 2.418 35.104 27.912 ;
     RECT  35.104 12.528 35.165 12.552 ;
     RECT  35.104 15.888 35.309 19.416 ;
     RECT  35.309 15.888 35.315 19.32 ;
     RECT  35.315 18.432 35.363 19.224 ;
     RECT  35.104 25.632 35.363 27.912 ;
     RECT  35.104 10.272 35.453 11.4 ;
     RECT  35.077 29.712 35.461 30.168 ;
     RECT  35.461 29.616 35.557 30.168 ;
     RECT  35.557 29.568 35.669 30.168 ;
     RECT  35.669 29.616 35.741 30.168 ;
     RECT  35.453 10.32 35.777 11.4 ;
     RECT  35.777 10.56 35.885 11.4 ;
     RECT  35.363 25.632 36.065 25.656 ;
     RECT  35.885 10.56 36.137 10.584 ;
     RECT  35.315 15.888 36.421 17.448 ;
     RECT  35.363 26.64 36.613 27.912 ;
     RECT  36.421 15.888 36.709 17.64 ;
     RECT  36.133 25.056 37.045 25.08 ;
     RECT  35.741 30.144 37.045 30.168 ;
     RECT  37.045 30.048 37.333 30.168 ;
     RECT  36.709 15.84 37.381 17.64 ;
     RECT  35.104 13.584 37.508 14.232 ;
     RECT  37.381 15.36 37.508 17.64 ;
     RECT  37.045 25.008 37.508 25.08 ;
     RECT  36.613 26.64 37.508 28.488 ;
     RECT  37.508 2.148 37.612 28.488 ;
     RECT  37.612 2.418 37.628 28.488 ;
     RECT  37.628 2.418 37.715 28.536 ;
     RECT  37.715 2.418 37.804 28.488 ;
     RECT  37.333 30 37.861 30.168 ;
     RECT  37.861 29.952 38.051 30.168 ;
     RECT  37.804 25.68 38.195 28.488 ;
     RECT  38.195 26.64 38.657 28.488 ;
     RECT  37.804 15.552 38.765 18.312 ;
     RECT  38.765 15.552 38.797 17.928 ;
     RECT  38.657 26.64 38.801 27.912 ;
     RECT  38.797 15.456 38.909 17.928 ;
     RECT  37.804 13.584 40.208 13.896 ;
     RECT  38.909 16.032 40.208 17.928 ;
     RECT  37.804 20.448 40.208 20.52 ;
     RECT  38.801 26.64 40.208 27.192 ;
     RECT  40.208 2.148 40.312 27.552 ;
     RECT  40.312 2.418 40.4 27.552 ;
     RECT  40.4 2.418 40.504 27.822 ;
     RECT  40.504 16.032 41.033 17.928 ;
     RECT  40.504 13.584 42.908 13.896 ;
     RECT  41.033 16.032 42.908 17.448 ;
     RECT  40.504 26.64 42.908 27.192 ;
     RECT  42.908 2.148 43.012 27.552 ;
     RECT  43.012 2.418 43.1 27.552 ;
     RECT  43.1 2.418 43.204 27.822 ;
     RECT  38.051 30.144 45.173 30.168 ;
     RECT  43.204 13.584 45.253 13.896 ;
     RECT  45.253 13.344 45.349 13.896 ;
     RECT  45.349 13.344 45.608 14.136 ;
     RECT  43.204 16.032 45.608 17.448 ;
     RECT  45.341 21.072 45.608 21.096 ;
     RECT  43.204 26.64 45.608 27.192 ;
     RECT  45.608 2.148 45.712 27.552 ;
     RECT  45.712 2.418 45.8 27.552 ;
     RECT  45.8 2.418 45.904 27.822 ;
     RECT  45.904 12.816 46.001 14.136 ;
     RECT  45.904 15.504 46.067 17.448 ;
     RECT  45.904 21.12 46.073 21.144 ;
     RECT  46.001 12.816 46.163 13.704 ;
     RECT  45.904 26.64 46.793 27.192 ;
     RECT  47.581 18.816 47.64 18.84 ;
     RECT  46.163 12.816 48.308 13.32 ;
     RECT  46.067 15.504 48.308 16.872 ;
     RECT  47.64 18.768 48.308 18.84 ;
     RECT  46.793 26.64 48.308 26.664 ;
     RECT  48.308 2.148 48.412 27.552 ;
     RECT  48.412 2.418 48.5 27.552 ;
     RECT  48.5 2.418 48.604 27.822 ;
     RECT  48.604 12.816 50.713 13.32 ;
     RECT  50.713 12.576 51.008 13.32 ;
     RECT  48.604 15.504 51.008 16.824 ;
     RECT  48.604 18.768 51.008 18.792 ;
     RECT  51.008 2.148 51.112 27.552 ;
     RECT  51.112 2.418 51.2 27.552 ;
     RECT  51.2 2.418 51.304 27.822 ;
     RECT  51.304 12.576 53.708 13.32 ;
     RECT  51.304 15.504 53.708 16.824 ;
     RECT  51.304 18.768 53.708 18.792 ;
     RECT  53.708 2.148 53.812 27.552 ;
     RECT  53.812 2.418 53.9 27.552 ;
     RECT  53.9 2.418 54.004 27.822 ;
     RECT  54.004 11.52 55.177 11.544 ;
     RECT  54.004 15.504 55.217 18.792 ;
     RECT  55.177 11.328 55.249 11.544 ;
     RECT  54.004 12.576 55.573 13.32 ;
     RECT  55.249 10.368 55.669 11.544 ;
     RECT  55.573 12.576 55.669 13.944 ;
     RECT  55.217 15.504 55.689 18.264 ;
     RECT  55.321 8.496 55.909 8.52 ;
     RECT  55.669 10.368 56.077 13.944 ;
     RECT  56.077 10.368 56.365 14.184 ;
     RECT  55.689 15.36 56.365 18.264 ;
     RECT  55.909 8.496 56.408 9.384 ;
     RECT  56.365 10.368 56.408 18.264 ;
     RECT  55.621 19.392 56.408 19.416 ;
     RECT  56.408 2.148 56.512 27.552 ;
     RECT  56.512 2.418 56.6 27.552 ;
     RECT  56.6 2.418 56.704 27.822 ;
     RECT  56.704 7.632 56.909 8.472 ;
     RECT  56.704 11.424 56.945 17.16 ;
     RECT  56.704 9.696 57.011 10.296 ;
     RECT  56.909 7.92 57.089 8.472 ;
     RECT  57.011 10.272 57.697 10.296 ;
     RECT  56.945 11.424 57.697 11.448 ;
     RECT  56.945 12.528 57.697 17.16 ;
     RECT  57.697 12.528 57.836 17.208 ;
     RECT  57.836 12.528 57.923 17.64 ;
     RECT  56.704 18.864 58.061 18.888 ;
     RECT  57.805 9.072 58.117 9.096 ;
     RECT  57.697 10.272 58.117 11.448 ;
     RECT  58.117 9.072 58.273 11.448 ;
     RECT  57.923 12.528 58.273 17.208 ;
     RECT  58.273 9.072 58.633 17.208 ;
     RECT  57.089 7.92 58.669 7.944 ;
     RECT  58.633 9.024 58.669 17.208 ;
     RECT  58.669 7.92 58.741 17.208 ;
     RECT  58.741 7.2 58.885 17.208 ;
     RECT  58.885 7.2 59.108 18.168 ;
     RECT  59.101 19.248 59.108 19.272 ;
     RECT  59.108 2.148 59.212 27.552 ;
     RECT  59.212 2.418 59.3 27.552 ;
     RECT  59.3 2.418 59.404 27.822 ;
     RECT  59.404 6.912 60.329 6.936 ;
     RECT  59.404 7.92 60.473 19.416 ;
     RECT  60.473 7.92 60.973 18.696 ;
     RECT  60.973 7.632 61.808 18.696 ;
     RECT  61.808 2.148 61.912 27.552 ;
     RECT  61.912 2.418 62 27.552 ;
     RECT  62 2.418 62.104 27.822 ;
     RECT  62.104 7.056 63.853 19.08 ;
     RECT  63.853 6.864 64.716 19.08 ;
     RECT  64.716 7.488 64.757 7.512 ;
     RECT  64.716 10.176 64.757 10.2 ;
     RECT  64.716 15.84 64.757 15.864 ;
    LAYER M5 ;
     RECT  2.4 2.137 2.52 2.151 ;
     RECT  5.1 2.137 5.22 2.151 ;
     RECT  7.8 2.137 7.92 2.151 ;
     RECT  10.5 2.137 10.62 2.151 ;
     RECT  13.2 2.137 13.32 2.151 ;
     RECT  15.9 2.137 16.02 2.151 ;
     RECT  18.6 2.137 18.72 2.151 ;
     RECT  21.3 2.137 21.42 2.151 ;
     RECT  24 2.137 24.12 2.151 ;
     RECT  26.7 2.137 26.82 2.151 ;
     RECT  29.4 2.137 29.52 2.151 ;
     RECT  32.1 2.137 32.22 2.151 ;
     RECT  34.8 2.137 34.92 2.151 ;
     RECT  37.5 2.137 37.62 2.151 ;
     RECT  40.2 2.137 40.32 2.151 ;
     RECT  42.9 2.137 43.02 2.151 ;
     RECT  45.6 2.137 45.72 2.151 ;
     RECT  48.3 2.137 48.42 2.151 ;
     RECT  51 2.137 51.12 2.151 ;
     RECT  53.7 2.137 53.82 2.151 ;
     RECT  56.4 2.137 56.52 2.151 ;
     RECT  59.1 2.137 59.22 2.151 ;
     RECT  61.8 2.137 61.92 2.151 ;
     RECT  32.1 2.151 32.412 7.957 ;
     RECT  60.672 7.957 60.696 8.435 ;
     RECT  56.4 2.151 56.712 8.437 ;
     RECT  32.1 7.957 32.808 8.533 ;
     RECT  59.1 2.151 59.412 9.013 ;
     RECT  60.48 8.965 60.504 9.013 ;
     RECT  59.1 9.013 60.504 9.061 ;
     RECT  56.4 8.437 57 9.349 ;
     RECT  55.92 9.349 57 9.731 ;
     RECT  34.8 2.151 35.112 9.781 ;
     RECT  58.272 9.061 60.504 9.781 ;
     RECT  34.416 9.781 35.112 10.261 ;
     RECT  34.416 10.261 35.208 10.309 ;
     RECT  55.92 9.731 56.856 10.597 ;
     RECT  58.128 9.781 60.504 10.931 ;
     RECT  29.4 2.151 29.712 10.981 ;
     RECT  58.128 10.931 60.12 11.123 ;
     RECT  55.392 10.597 56.856 11.363 ;
     RECT  32.1 8.533 32.904 11.365 ;
     RECT  34.416 10.309 35.304 11.365 ;
     RECT  29.4 10.981 29.832 11.845 ;
     RECT  32.1 11.365 33.288 11.941 ;
     RECT  34.416 11.365 35.4 11.941 ;
     RECT  55.68 11.363 56.856 12.755 ;
     RECT  45.6 2.151 45.912 12.805 ;
     RECT  29.4 11.845 30.6 13.093 ;
     RECT  55.68 12.755 56.712 13.331 ;
     RECT  45.6 12.805 46.152 13.333 ;
     RECT  29.4 13.093 30.888 13.525 ;
     RECT  32.1 11.941 35.4 13.525 ;
     RECT  2.4 2.151 2.712 13.621 ;
     RECT  3.936 13.573 3.96 13.621 ;
     RECT  45.264 13.333 46.152 13.715 ;
     RECT  58.128 11.123 59.412 13.765 ;
     RECT  57.744 13.765 59.412 13.811 ;
     RECT  29.4 13.525 35.4 14.005 ;
     RECT  29.4 14.005 35.688 14.149 ;
     RECT  37.5 2.151 37.812 14.149 ;
     RECT  2.4 13.621 3.96 14.291 ;
     RECT  59.1 13.811 59.412 14.821 ;
     RECT  60.384 13.285 60.408 14.821 ;
     RECT  59.1 14.821 60.408 14.867 ;
     RECT  0.144 14.629 0.168 14.963 ;
     RECT  55.728 13.331 56.712 15.395 ;
     RECT  45.264 13.715 45.912 15.493 ;
     RECT  2.4 14.291 3.576 16.019 ;
     RECT  2.4 16.019 3.144 16.067 ;
     RECT  29.4 14.149 37.812 16.357 ;
     RECT  56.4 15.395 56.712 16.405 ;
     RECT  48.3 2.151 48.612 16.789 ;
     RECT  55.44 16.405 56.712 16.835 ;
     RECT  45.264 15.493 46.056 16.883 ;
     RECT  57.744 13.811 57.768 17.123 ;
     RECT  26.7 2.151 27.012 17.461 ;
     RECT  29.4 16.357 38.088 17.893 ;
     RECT  26.7 17.461 27.336 17.989 ;
     RECT  26.7 17.989 27.768 18.037 ;
     RECT  56.4 16.835 56.712 18.133 ;
     RECT  47.616 16.789 48.612 18.851 ;
     RECT  57.888 17.605 57.912 18.899 ;
     RECT  26.7 18.037 27.912 18.997 ;
     RECT  26.7 18.997 28.392 19.285 ;
     RECT  29.4 17.893 38.376 19.285 ;
     RECT  55.632 18.133 56.712 19.427 ;
     RECT  59.1 14.867 60.264 19.427 ;
     RECT  26.7 19.285 38.376 19.861 ;
     RECT  26.592 19.861 38.376 20.437 ;
     RECT  45.36 16.883 46.056 21.107 ;
     RECT  45.6 21.107 46.056 21.155 ;
     RECT  26.592 20.437 38.664 25.045 ;
     RECT  47.712 18.851 48.612 26.675 ;
     RECT  2.4 16.067 2.712 27.819 ;
     RECT  5.1 2.151 5.412 27.819 ;
     RECT  7.8 2.151 8.112 27.819 ;
     RECT  10.5 2.151 10.812 27.819 ;
     RECT  13.2 2.151 13.512 27.819 ;
     RECT  15.9 2.151 16.212 27.819 ;
     RECT  18.6 2.151 18.912 27.819 ;
     RECT  21.3 2.151 21.612 27.819 ;
     RECT  24 2.151 24.312 27.819 ;
     RECT  40.2 2.151 40.512 27.819 ;
     RECT  42.9 2.151 43.212 27.819 ;
     RECT  45.6 21.155 45.912 27.819 ;
     RECT  48.3 26.675 48.612 27.819 ;
     RECT  51 2.151 51.312 27.819 ;
     RECT  53.7 2.151 54.012 27.819 ;
     RECT  56.4 19.427 56.712 27.819 ;
     RECT  59.1 19.427 59.412 27.819 ;
     RECT  61.8 2.151 62.112 27.819 ;
     RECT  2.592 27.819 2.712 27.833 ;
     RECT  5.292 27.819 5.412 27.833 ;
     RECT  7.992 27.819 8.112 27.833 ;
     RECT  10.692 27.819 10.812 27.833 ;
     RECT  13.392 27.819 13.512 27.833 ;
     RECT  16.092 27.819 16.212 27.833 ;
     RECT  18.792 27.819 18.912 27.833 ;
     RECT  21.492 27.819 21.612 27.833 ;
     RECT  24.192 27.819 24.312 27.833 ;
     RECT  40.392 27.819 40.512 27.833 ;
     RECT  43.092 27.819 43.212 27.833 ;
     RECT  45.792 27.819 45.912 27.833 ;
     RECT  48.492 27.819 48.612 27.833 ;
     RECT  51.192 27.819 51.312 27.833 ;
     RECT  53.892 27.819 54.012 27.833 ;
     RECT  56.592 27.819 56.712 27.833 ;
     RECT  59.292 27.819 59.412 27.833 ;
     RECT  61.992 27.819 62.112 27.833 ;
     RECT  26.448 25.045 38.664 30.16 ;
  END
END qfd_rlyh0_128_EN_65x30
END LIBRARY
